# Generated by FakeRAM 2.0
VERSION 5.7 ;
BUSBITCHARS "[]" ;
PROPERTYDEFINITIONS
  MACRO width INTEGER ;
  MACRO depth INTEGER ;
  MACRO banks INTEGER ;
END PROPERTYDEFINITIONS
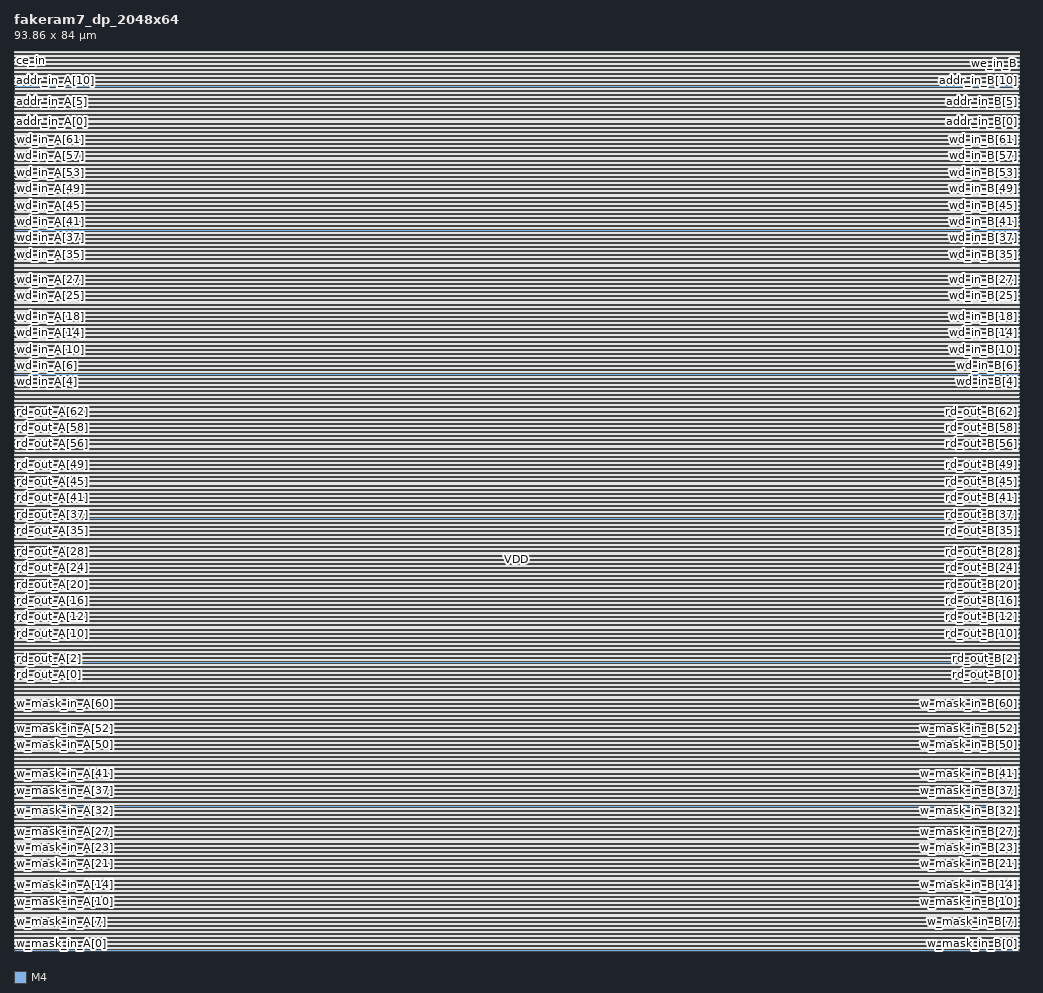
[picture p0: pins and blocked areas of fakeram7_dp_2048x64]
MACRO fakeram7_dp_2048x64
  PROPERTY width 64 ;
  PROPERTY depth 2048 ;
  PROPERTY banks 8 ;
  FOREIGN fakeram7_dp_2048x64 0 0 ;
  SYMMETRY X Y ;
  SIZE 93.860 BY 84.000 ;
  CLASS BLOCK ;
  PIN w_mask_in_A[0]
    DIRECTION INPUT ;
    USE SIGNAL ;
    SHAPE ABUTMENT ;
    PORT
      LAYER M4 ;
      RECT 0.000 0.048 0.024 0.072 ;
    END
  END w_mask_in_A[0]
  PIN w_mask_in_B[0]
    DIRECTION INPUT ;
    USE SIGNAL ;
    SHAPE ABUTMENT ;
    PORT
      LAYER M4 ;
      RECT 93.836 0.048 93.860 0.072 ;
    END
  END w_mask_in_B[0]
  PIN w_mask_in_A[1]
    DIRECTION INPUT ;
    USE SIGNAL ;
    SHAPE ABUTMENT ;
    PORT
      LAYER M4 ;
      RECT 0.000 0.432 0.024 0.456 ;
    END
  END w_mask_in_A[1]
  PIN w_mask_in_B[1]
    DIRECTION INPUT ;
    USE SIGNAL ;
    SHAPE ABUTMENT ;
    PORT
      LAYER M4 ;
      RECT 93.836 0.432 93.860 0.456 ;
    END
  END w_mask_in_B[1]
  PIN w_mask_in_A[2]
    DIRECTION INPUT ;
    USE SIGNAL ;
    SHAPE ABUTMENT ;
    PORT
      LAYER M4 ;
      RECT 0.000 0.816 0.024 0.840 ;
    END
  END w_mask_in_A[2]
  PIN w_mask_in_B[2]
    DIRECTION INPUT ;
    USE SIGNAL ;
    SHAPE ABUTMENT ;
    PORT
      LAYER M4 ;
      RECT 93.836 0.816 93.860 0.840 ;
    END
  END w_mask_in_B[2]
  PIN w_mask_in_A[3]
    DIRECTION INPUT ;
    USE SIGNAL ;
    SHAPE ABUTMENT ;
    PORT
      LAYER M4 ;
      RECT 0.000 1.200 0.024 1.224 ;
    END
  END w_mask_in_A[3]
  PIN w_mask_in_B[3]
    DIRECTION INPUT ;
    USE SIGNAL ;
    SHAPE ABUTMENT ;
    PORT
      LAYER M4 ;
      RECT 93.836 1.200 93.860 1.224 ;
    END
  END w_mask_in_B[3]
  PIN w_mask_in_A[4]
    DIRECTION INPUT ;
    USE SIGNAL ;
    SHAPE ABUTMENT ;
    PORT
      LAYER M4 ;
      RECT 0.000 1.584 0.024 1.608 ;
    END
  END w_mask_in_A[4]
  PIN w_mask_in_B[4]
    DIRECTION INPUT ;
    USE SIGNAL ;
    SHAPE ABUTMENT ;
    PORT
      LAYER M4 ;
      RECT 93.836 1.584 93.860 1.608 ;
    END
  END w_mask_in_B[4]
  PIN w_mask_in_A[5]
    DIRECTION INPUT ;
    USE SIGNAL ;
    SHAPE ABUTMENT ;
    PORT
      LAYER M4 ;
      RECT 0.000 1.968 0.024 1.992 ;
    END
  END w_mask_in_A[5]
  PIN w_mask_in_B[5]
    DIRECTION INPUT ;
    USE SIGNAL ;
    SHAPE ABUTMENT ;
    PORT
      LAYER M4 ;
      RECT 93.836 1.968 93.860 1.992 ;
    END
  END w_mask_in_B[5]
  PIN w_mask_in_A[6]
    DIRECTION INPUT ;
    USE SIGNAL ;
    SHAPE ABUTMENT ;
    PORT
      LAYER M4 ;
      RECT 0.000 2.352 0.024 2.376 ;
    END
  END w_mask_in_A[6]
  PIN w_mask_in_B[6]
    DIRECTION INPUT ;
    USE SIGNAL ;
    SHAPE ABUTMENT ;
    PORT
      LAYER M4 ;
      RECT 93.836 2.352 93.860 2.376 ;
    END
  END w_mask_in_B[6]
  PIN w_mask_in_A[7]
    DIRECTION INPUT ;
    USE SIGNAL ;
    SHAPE ABUTMENT ;
    PORT
      LAYER M4 ;
      RECT 0.000 2.736 0.024 2.760 ;
    END
  END w_mask_in_A[7]
  PIN w_mask_in_B[7]
    DIRECTION INPUT ;
    USE SIGNAL ;
    SHAPE ABUTMENT ;
    PORT
      LAYER M4 ;
      RECT 93.836 2.736 93.860 2.760 ;
    END
  END w_mask_in_B[7]
  PIN w_mask_in_A[8]
    DIRECTION INPUT ;
    USE SIGNAL ;
    SHAPE ABUTMENT ;
    PORT
      LAYER M4 ;
      RECT 0.000 3.120 0.024 3.144 ;
    END
  END w_mask_in_A[8]
  PIN w_mask_in_B[8]
    DIRECTION INPUT ;
    USE SIGNAL ;
    SHAPE ABUTMENT ;
    PORT
      LAYER M4 ;
      RECT 93.836 3.120 93.860 3.144 ;
    END
  END w_mask_in_B[8]
  PIN w_mask_in_A[9]
    DIRECTION INPUT ;
    USE SIGNAL ;
    SHAPE ABUTMENT ;
    PORT
      LAYER M4 ;
      RECT 0.000 3.504 0.024 3.528 ;
    END
  END w_mask_in_A[9]
  PIN w_mask_in_B[9]
    DIRECTION INPUT ;
    USE SIGNAL ;
    SHAPE ABUTMENT ;
    PORT
      LAYER M4 ;
      RECT 93.836 3.504 93.860 3.528 ;
    END
  END w_mask_in_B[9]
  PIN w_mask_in_A[10]
    DIRECTION INPUT ;
    USE SIGNAL ;
    SHAPE ABUTMENT ;
    PORT
      LAYER M4 ;
      RECT 0.000 3.888 0.024 3.912 ;
    END
  END w_mask_in_A[10]
  PIN w_mask_in_B[10]
    DIRECTION INPUT ;
    USE SIGNAL ;
    SHAPE ABUTMENT ;
    PORT
      LAYER M4 ;
      RECT 93.836 3.888 93.860 3.912 ;
    END
  END w_mask_in_B[10]
  PIN w_mask_in_A[11]
    DIRECTION INPUT ;
    USE SIGNAL ;
    SHAPE ABUTMENT ;
    PORT
      LAYER M4 ;
      RECT 0.000 4.272 0.024 4.296 ;
    END
  END w_mask_in_A[11]
  PIN w_mask_in_B[11]
    DIRECTION INPUT ;
    USE SIGNAL ;
    SHAPE ABUTMENT ;
    PORT
      LAYER M4 ;
      RECT 93.836 4.272 93.860 4.296 ;
    END
  END w_mask_in_B[11]
  PIN w_mask_in_A[12]
    DIRECTION INPUT ;
    USE SIGNAL ;
    SHAPE ABUTMENT ;
    PORT
      LAYER M4 ;
      RECT 0.000 4.656 0.024 4.680 ;
    END
  END w_mask_in_A[12]
  PIN w_mask_in_B[12]
    DIRECTION INPUT ;
    USE SIGNAL ;
    SHAPE ABUTMENT ;
    PORT
      LAYER M4 ;
      RECT 93.836 4.656 93.860 4.680 ;
    END
  END w_mask_in_B[12]
  PIN w_mask_in_A[13]
    DIRECTION INPUT ;
    USE SIGNAL ;
    SHAPE ABUTMENT ;
    PORT
      LAYER M4 ;
      RECT 0.000 5.040 0.024 5.064 ;
    END
  END w_mask_in_A[13]
  PIN w_mask_in_B[13]
    DIRECTION INPUT ;
    USE SIGNAL ;
    SHAPE ABUTMENT ;
    PORT
      LAYER M4 ;
      RECT 93.836 5.040 93.860 5.064 ;
    END
  END w_mask_in_B[13]
  PIN w_mask_in_A[14]
    DIRECTION INPUT ;
    USE SIGNAL ;
    SHAPE ABUTMENT ;
    PORT
      LAYER M4 ;
      RECT 0.000 5.424 0.024 5.448 ;
    END
  END w_mask_in_A[14]
  PIN w_mask_in_B[14]
    DIRECTION INPUT ;
    USE SIGNAL ;
    SHAPE ABUTMENT ;
    PORT
      LAYER M4 ;
      RECT 93.836 5.424 93.860 5.448 ;
    END
  END w_mask_in_B[14]
  PIN w_mask_in_A[15]
    DIRECTION INPUT ;
    USE SIGNAL ;
    SHAPE ABUTMENT ;
    PORT
      LAYER M4 ;
      RECT 0.000 5.808 0.024 5.832 ;
    END
  END w_mask_in_A[15]
  PIN w_mask_in_B[15]
    DIRECTION INPUT ;
    USE SIGNAL ;
    SHAPE ABUTMENT ;
    PORT
      LAYER M4 ;
      RECT 93.836 5.808 93.860 5.832 ;
    END
  END w_mask_in_B[15]
  PIN w_mask_in_A[16]
    DIRECTION INPUT ;
    USE SIGNAL ;
    SHAPE ABUTMENT ;
    PORT
      LAYER M4 ;
      RECT 0.000 6.192 0.024 6.216 ;
    END
  END w_mask_in_A[16]
  PIN w_mask_in_B[16]
    DIRECTION INPUT ;
    USE SIGNAL ;
    SHAPE ABUTMENT ;
    PORT
      LAYER M4 ;
      RECT 93.836 6.192 93.860 6.216 ;
    END
  END w_mask_in_B[16]
  PIN w_mask_in_A[17]
    DIRECTION INPUT ;
    USE SIGNAL ;
    SHAPE ABUTMENT ;
    PORT
      LAYER M4 ;
      RECT 0.000 6.576 0.024 6.600 ;
    END
  END w_mask_in_A[17]
  PIN w_mask_in_B[17]
    DIRECTION INPUT ;
    USE SIGNAL ;
    SHAPE ABUTMENT ;
    PORT
      LAYER M4 ;
      RECT 93.836 6.576 93.860 6.600 ;
    END
  END w_mask_in_B[17]
  PIN w_mask_in_A[18]
    DIRECTION INPUT ;
    USE SIGNAL ;
    SHAPE ABUTMENT ;
    PORT
      LAYER M4 ;
      RECT 0.000 6.960 0.024 6.984 ;
    END
  END w_mask_in_A[18]
  PIN w_mask_in_B[18]
    DIRECTION INPUT ;
    USE SIGNAL ;
    SHAPE ABUTMENT ;
    PORT
      LAYER M4 ;
      RECT 93.836 6.960 93.860 6.984 ;
    END
  END w_mask_in_B[18]
  PIN w_mask_in_A[19]
    DIRECTION INPUT ;
    USE SIGNAL ;
    SHAPE ABUTMENT ;
    PORT
      LAYER M4 ;
      RECT 0.000 7.344 0.024 7.368 ;
    END
  END w_mask_in_A[19]
  PIN w_mask_in_B[19]
    DIRECTION INPUT ;
    USE SIGNAL ;
    SHAPE ABUTMENT ;
    PORT
      LAYER M4 ;
      RECT 93.836 7.344 93.860 7.368 ;
    END
  END w_mask_in_B[19]
  PIN w_mask_in_A[20]
    DIRECTION INPUT ;
    USE SIGNAL ;
    SHAPE ABUTMENT ;
    PORT
      LAYER M4 ;
      RECT 0.000 7.728 0.024 7.752 ;
    END
  END w_mask_in_A[20]
  PIN w_mask_in_B[20]
    DIRECTION INPUT ;
    USE SIGNAL ;
    SHAPE ABUTMENT ;
    PORT
      LAYER M4 ;
      RECT 93.836 7.728 93.860 7.752 ;
    END
  END w_mask_in_B[20]
  PIN w_mask_in_A[21]
    DIRECTION INPUT ;
    USE SIGNAL ;
    SHAPE ABUTMENT ;
    PORT
      LAYER M4 ;
      RECT 0.000 8.112 0.024 8.136 ;
    END
  END w_mask_in_A[21]
  PIN w_mask_in_B[21]
    DIRECTION INPUT ;
    USE SIGNAL ;
    SHAPE ABUTMENT ;
    PORT
      LAYER M4 ;
      RECT 93.836 8.112 93.860 8.136 ;
    END
  END w_mask_in_B[21]
  PIN w_mask_in_A[22]
    DIRECTION INPUT ;
    USE SIGNAL ;
    SHAPE ABUTMENT ;
    PORT
      LAYER M4 ;
      RECT 0.000 8.496 0.024 8.520 ;
    END
  END w_mask_in_A[22]
  PIN w_mask_in_B[22]
    DIRECTION INPUT ;
    USE SIGNAL ;
    SHAPE ABUTMENT ;
    PORT
      LAYER M4 ;
      RECT 93.836 8.496 93.860 8.520 ;
    END
  END w_mask_in_B[22]
  PIN w_mask_in_A[23]
    DIRECTION INPUT ;
    USE SIGNAL ;
    SHAPE ABUTMENT ;
    PORT
      LAYER M4 ;
      RECT 0.000 8.880 0.024 8.904 ;
    END
  END w_mask_in_A[23]
  PIN w_mask_in_B[23]
    DIRECTION INPUT ;
    USE SIGNAL ;
    SHAPE ABUTMENT ;
    PORT
      LAYER M4 ;
      RECT 93.836 8.880 93.860 8.904 ;
    END
  END w_mask_in_B[23]
  PIN w_mask_in_A[24]
    DIRECTION INPUT ;
    USE SIGNAL ;
    SHAPE ABUTMENT ;
    PORT
      LAYER M4 ;
      RECT 0.000 9.264 0.024 9.288 ;
    END
  END w_mask_in_A[24]
  PIN w_mask_in_B[24]
    DIRECTION INPUT ;
    USE SIGNAL ;
    SHAPE ABUTMENT ;
    PORT
      LAYER M4 ;
      RECT 93.836 9.264 93.860 9.288 ;
    END
  END w_mask_in_B[24]
  PIN w_mask_in_A[25]
    DIRECTION INPUT ;
    USE SIGNAL ;
    SHAPE ABUTMENT ;
    PORT
      LAYER M4 ;
      RECT 0.000 9.648 0.024 9.672 ;
    END
  END w_mask_in_A[25]
  PIN w_mask_in_B[25]
    DIRECTION INPUT ;
    USE SIGNAL ;
    SHAPE ABUTMENT ;
    PORT
      LAYER M4 ;
      RECT 93.836 9.648 93.860 9.672 ;
    END
  END w_mask_in_B[25]
  PIN w_mask_in_A[26]
    DIRECTION INPUT ;
    USE SIGNAL ;
    SHAPE ABUTMENT ;
    PORT
      LAYER M4 ;
      RECT 0.000 10.032 0.024 10.056 ;
    END
  END w_mask_in_A[26]
  PIN w_mask_in_B[26]
    DIRECTION INPUT ;
    USE SIGNAL ;
    SHAPE ABUTMENT ;
    PORT
      LAYER M4 ;
      RECT 93.836 10.032 93.860 10.056 ;
    END
  END w_mask_in_B[26]
  PIN w_mask_in_A[27]
    DIRECTION INPUT ;
    USE SIGNAL ;
    SHAPE ABUTMENT ;
    PORT
      LAYER M4 ;
      RECT 0.000 10.416 0.024 10.440 ;
    END
  END w_mask_in_A[27]
  PIN w_mask_in_B[27]
    DIRECTION INPUT ;
    USE SIGNAL ;
    SHAPE ABUTMENT ;
    PORT
      LAYER M4 ;
      RECT 93.836 10.416 93.860 10.440 ;
    END
  END w_mask_in_B[27]
  PIN w_mask_in_A[28]
    DIRECTION INPUT ;
    USE SIGNAL ;
    SHAPE ABUTMENT ;
    PORT
      LAYER M4 ;
      RECT 0.000 10.800 0.024 10.824 ;
    END
  END w_mask_in_A[28]
  PIN w_mask_in_B[28]
    DIRECTION INPUT ;
    USE SIGNAL ;
    SHAPE ABUTMENT ;
    PORT
      LAYER M4 ;
      RECT 93.836 10.800 93.860 10.824 ;
    END
  END w_mask_in_B[28]
  PIN w_mask_in_A[29]
    DIRECTION INPUT ;
    USE SIGNAL ;
    SHAPE ABUTMENT ;
    PORT
      LAYER M4 ;
      RECT 0.000 11.184 0.024 11.208 ;
    END
  END w_mask_in_A[29]
  PIN w_mask_in_B[29]
    DIRECTION INPUT ;
    USE SIGNAL ;
    SHAPE ABUTMENT ;
    PORT
      LAYER M4 ;
      RECT 93.836 11.184 93.860 11.208 ;
    END
  END w_mask_in_B[29]
  PIN w_mask_in_A[30]
    DIRECTION INPUT ;
    USE SIGNAL ;
    SHAPE ABUTMENT ;
    PORT
      LAYER M4 ;
      RECT 0.000 11.568 0.024 11.592 ;
    END
  END w_mask_in_A[30]
  PIN w_mask_in_B[30]
    DIRECTION INPUT ;
    USE SIGNAL ;
    SHAPE ABUTMENT ;
    PORT
      LAYER M4 ;
      RECT 93.836 11.568 93.860 11.592 ;
    END
  END w_mask_in_B[30]
  PIN w_mask_in_A[31]
    DIRECTION INPUT ;
    USE SIGNAL ;
    SHAPE ABUTMENT ;
    PORT
      LAYER M4 ;
      RECT 0.000 11.952 0.024 11.976 ;
    END
  END w_mask_in_A[31]
  PIN w_mask_in_B[31]
    DIRECTION INPUT ;
    USE SIGNAL ;
    SHAPE ABUTMENT ;
    PORT
      LAYER M4 ;
      RECT 93.836 11.952 93.860 11.976 ;
    END
  END w_mask_in_B[31]
  PIN w_mask_in_A[32]
    DIRECTION INPUT ;
    USE SIGNAL ;
    SHAPE ABUTMENT ;
    PORT
      LAYER M4 ;
      RECT 0.000 12.336 0.024 12.360 ;
    END
  END w_mask_in_A[32]
  PIN w_mask_in_B[32]
    DIRECTION INPUT ;
    USE SIGNAL ;
    SHAPE ABUTMENT ;
    PORT
      LAYER M4 ;
      RECT 93.836 12.336 93.860 12.360 ;
    END
  END w_mask_in_B[32]
  PIN w_mask_in_A[33]
    DIRECTION INPUT ;
    USE SIGNAL ;
    SHAPE ABUTMENT ;
    PORT
      LAYER M4 ;
      RECT 0.000 12.720 0.024 12.744 ;
    END
  END w_mask_in_A[33]
  PIN w_mask_in_B[33]
    DIRECTION INPUT ;
    USE SIGNAL ;
    SHAPE ABUTMENT ;
    PORT
      LAYER M4 ;
      RECT 93.836 12.720 93.860 12.744 ;
    END
  END w_mask_in_B[33]
  PIN w_mask_in_A[34]
    DIRECTION INPUT ;
    USE SIGNAL ;
    SHAPE ABUTMENT ;
    PORT
      LAYER M4 ;
      RECT 0.000 13.104 0.024 13.128 ;
    END
  END w_mask_in_A[34]
  PIN w_mask_in_B[34]
    DIRECTION INPUT ;
    USE SIGNAL ;
    SHAPE ABUTMENT ;
    PORT
      LAYER M4 ;
      RECT 93.836 13.104 93.860 13.128 ;
    END
  END w_mask_in_B[34]
  PIN w_mask_in_A[35]
    DIRECTION INPUT ;
    USE SIGNAL ;
    SHAPE ABUTMENT ;
    PORT
      LAYER M4 ;
      RECT 0.000 13.488 0.024 13.512 ;
    END
  END w_mask_in_A[35]
  PIN w_mask_in_B[35]
    DIRECTION INPUT ;
    USE SIGNAL ;
    SHAPE ABUTMENT ;
    PORT
      LAYER M4 ;
      RECT 93.836 13.488 93.860 13.512 ;
    END
  END w_mask_in_B[35]
  PIN w_mask_in_A[36]
    DIRECTION INPUT ;
    USE SIGNAL ;
    SHAPE ABUTMENT ;
    PORT
      LAYER M4 ;
      RECT 0.000 13.872 0.024 13.896 ;
    END
  END w_mask_in_A[36]
  PIN w_mask_in_B[36]
    DIRECTION INPUT ;
    USE SIGNAL ;
    SHAPE ABUTMENT ;
    PORT
      LAYER M4 ;
      RECT 93.836 13.872 93.860 13.896 ;
    END
  END w_mask_in_B[36]
  PIN w_mask_in_A[37]
    DIRECTION INPUT ;
    USE SIGNAL ;
    SHAPE ABUTMENT ;
    PORT
      LAYER M4 ;
      RECT 0.000 14.256 0.024 14.280 ;
    END
  END w_mask_in_A[37]
  PIN w_mask_in_B[37]
    DIRECTION INPUT ;
    USE SIGNAL ;
    SHAPE ABUTMENT ;
    PORT
      LAYER M4 ;
      RECT 93.836 14.256 93.860 14.280 ;
    END
  END w_mask_in_B[37]
  PIN w_mask_in_A[38]
    DIRECTION INPUT ;
    USE SIGNAL ;
    SHAPE ABUTMENT ;
    PORT
      LAYER M4 ;
      RECT 0.000 14.640 0.024 14.664 ;
    END
  END w_mask_in_A[38]
  PIN w_mask_in_B[38]
    DIRECTION INPUT ;
    USE SIGNAL ;
    SHAPE ABUTMENT ;
    PORT
      LAYER M4 ;
      RECT 93.836 14.640 93.860 14.664 ;
    END
  END w_mask_in_B[38]
  PIN w_mask_in_A[39]
    DIRECTION INPUT ;
    USE SIGNAL ;
    SHAPE ABUTMENT ;
    PORT
      LAYER M4 ;
      RECT 0.000 15.024 0.024 15.048 ;
    END
  END w_mask_in_A[39]
  PIN w_mask_in_B[39]
    DIRECTION INPUT ;
    USE SIGNAL ;
    SHAPE ABUTMENT ;
    PORT
      LAYER M4 ;
      RECT 93.836 15.024 93.860 15.048 ;
    END
  END w_mask_in_B[39]
  PIN w_mask_in_A[40]
    DIRECTION INPUT ;
    USE SIGNAL ;
    SHAPE ABUTMENT ;
    PORT
      LAYER M4 ;
      RECT 0.000 15.408 0.024 15.432 ;
    END
  END w_mask_in_A[40]
  PIN w_mask_in_B[40]
    DIRECTION INPUT ;
    USE SIGNAL ;
    SHAPE ABUTMENT ;
    PORT
      LAYER M4 ;
      RECT 93.836 15.408 93.860 15.432 ;
    END
  END w_mask_in_B[40]
  PIN w_mask_in_A[41]
    DIRECTION INPUT ;
    USE SIGNAL ;
    SHAPE ABUTMENT ;
    PORT
      LAYER M4 ;
      RECT 0.000 15.792 0.024 15.816 ;
    END
  END w_mask_in_A[41]
  PIN w_mask_in_B[41]
    DIRECTION INPUT ;
    USE SIGNAL ;
    SHAPE ABUTMENT ;
    PORT
      LAYER M4 ;
      RECT 93.836 15.792 93.860 15.816 ;
    END
  END w_mask_in_B[41]
  PIN w_mask_in_A[42]
    DIRECTION INPUT ;
    USE SIGNAL ;
    SHAPE ABUTMENT ;
    PORT
      LAYER M4 ;
      RECT 0.000 16.176 0.024 16.200 ;
    END
  END w_mask_in_A[42]
  PIN w_mask_in_B[42]
    DIRECTION INPUT ;
    USE SIGNAL ;
    SHAPE ABUTMENT ;
    PORT
      LAYER M4 ;
      RECT 93.836 16.176 93.860 16.200 ;
    END
  END w_mask_in_B[42]
  PIN w_mask_in_A[43]
    DIRECTION INPUT ;
    USE SIGNAL ;
    SHAPE ABUTMENT ;
    PORT
      LAYER M4 ;
      RECT 0.000 16.560 0.024 16.584 ;
    END
  END w_mask_in_A[43]
  PIN w_mask_in_B[43]
    DIRECTION INPUT ;
    USE SIGNAL ;
    SHAPE ABUTMENT ;
    PORT
      LAYER M4 ;
      RECT 93.836 16.560 93.860 16.584 ;
    END
  END w_mask_in_B[43]
  PIN w_mask_in_A[44]
    DIRECTION INPUT ;
    USE SIGNAL ;
    SHAPE ABUTMENT ;
    PORT
      LAYER M4 ;
      RECT 0.000 16.944 0.024 16.968 ;
    END
  END w_mask_in_A[44]
  PIN w_mask_in_B[44]
    DIRECTION INPUT ;
    USE SIGNAL ;
    SHAPE ABUTMENT ;
    PORT
      LAYER M4 ;
      RECT 93.836 16.944 93.860 16.968 ;
    END
  END w_mask_in_B[44]
  PIN w_mask_in_A[45]
    DIRECTION INPUT ;
    USE SIGNAL ;
    SHAPE ABUTMENT ;
    PORT
      LAYER M4 ;
      RECT 0.000 17.328 0.024 17.352 ;
    END
  END w_mask_in_A[45]
  PIN w_mask_in_B[45]
    DIRECTION INPUT ;
    USE SIGNAL ;
    SHAPE ABUTMENT ;
    PORT
      LAYER M4 ;
      RECT 93.836 17.328 93.860 17.352 ;
    END
  END w_mask_in_B[45]
  PIN w_mask_in_A[46]
    DIRECTION INPUT ;
    USE SIGNAL ;
    SHAPE ABUTMENT ;
    PORT
      LAYER M4 ;
      RECT 0.000 17.712 0.024 17.736 ;
    END
  END w_mask_in_A[46]
  PIN w_mask_in_B[46]
    DIRECTION INPUT ;
    USE SIGNAL ;
    SHAPE ABUTMENT ;
    PORT
      LAYER M4 ;
      RECT 93.836 17.712 93.860 17.736 ;
    END
  END w_mask_in_B[46]
  PIN w_mask_in_A[47]
    DIRECTION INPUT ;
    USE SIGNAL ;
    SHAPE ABUTMENT ;
    PORT
      LAYER M4 ;
      RECT 0.000 18.096 0.024 18.120 ;
    END
  END w_mask_in_A[47]
  PIN w_mask_in_B[47]
    DIRECTION INPUT ;
    USE SIGNAL ;
    SHAPE ABUTMENT ;
    PORT
      LAYER M4 ;
      RECT 93.836 18.096 93.860 18.120 ;
    END
  END w_mask_in_B[47]
  PIN w_mask_in_A[48]
    DIRECTION INPUT ;
    USE SIGNAL ;
    SHAPE ABUTMENT ;
    PORT
      LAYER M4 ;
      RECT 0.000 18.480 0.024 18.504 ;
    END
  END w_mask_in_A[48]
  PIN w_mask_in_B[48]
    DIRECTION INPUT ;
    USE SIGNAL ;
    SHAPE ABUTMENT ;
    PORT
      LAYER M4 ;
      RECT 93.836 18.480 93.860 18.504 ;
    END
  END w_mask_in_B[48]
  PIN w_mask_in_A[49]
    DIRECTION INPUT ;
    USE SIGNAL ;
    SHAPE ABUTMENT ;
    PORT
      LAYER M4 ;
      RECT 0.000 18.864 0.024 18.888 ;
    END
  END w_mask_in_A[49]
  PIN w_mask_in_B[49]
    DIRECTION INPUT ;
    USE SIGNAL ;
    SHAPE ABUTMENT ;
    PORT
      LAYER M4 ;
      RECT 93.836 18.864 93.860 18.888 ;
    END
  END w_mask_in_B[49]
  PIN w_mask_in_A[50]
    DIRECTION INPUT ;
    USE SIGNAL ;
    SHAPE ABUTMENT ;
    PORT
      LAYER M4 ;
      RECT 0.000 19.248 0.024 19.272 ;
    END
  END w_mask_in_A[50]
  PIN w_mask_in_B[50]
    DIRECTION INPUT ;
    USE SIGNAL ;
    SHAPE ABUTMENT ;
    PORT
      LAYER M4 ;
      RECT 93.836 19.248 93.860 19.272 ;
    END
  END w_mask_in_B[50]
  PIN w_mask_in_A[51]
    DIRECTION INPUT ;
    USE SIGNAL ;
    SHAPE ABUTMENT ;
    PORT
      LAYER M4 ;
      RECT 0.000 19.632 0.024 19.656 ;
    END
  END w_mask_in_A[51]
  PIN w_mask_in_B[51]
    DIRECTION INPUT ;
    USE SIGNAL ;
    SHAPE ABUTMENT ;
    PORT
      LAYER M4 ;
      RECT 93.836 19.632 93.860 19.656 ;
    END
  END w_mask_in_B[51]
  PIN w_mask_in_A[52]
    DIRECTION INPUT ;
    USE SIGNAL ;
    SHAPE ABUTMENT ;
    PORT
      LAYER M4 ;
      RECT 0.000 20.016 0.024 20.040 ;
    END
  END w_mask_in_A[52]
  PIN w_mask_in_B[52]
    DIRECTION INPUT ;
    USE SIGNAL ;
    SHAPE ABUTMENT ;
    PORT
      LAYER M4 ;
      RECT 93.836 20.016 93.860 20.040 ;
    END
  END w_mask_in_B[52]
  PIN w_mask_in_A[53]
    DIRECTION INPUT ;
    USE SIGNAL ;
    SHAPE ABUTMENT ;
    PORT
      LAYER M4 ;
      RECT 0.000 20.400 0.024 20.424 ;
    END
  END w_mask_in_A[53]
  PIN w_mask_in_B[53]
    DIRECTION INPUT ;
    USE SIGNAL ;
    SHAPE ABUTMENT ;
    PORT
      LAYER M4 ;
      RECT 93.836 20.400 93.860 20.424 ;
    END
  END w_mask_in_B[53]
  PIN w_mask_in_A[54]
    DIRECTION INPUT ;
    USE SIGNAL ;
    SHAPE ABUTMENT ;
    PORT
      LAYER M4 ;
      RECT 0.000 20.784 0.024 20.808 ;
    END
  END w_mask_in_A[54]
  PIN w_mask_in_B[54]
    DIRECTION INPUT ;
    USE SIGNAL ;
    SHAPE ABUTMENT ;
    PORT
      LAYER M4 ;
      RECT 93.836 20.784 93.860 20.808 ;
    END
  END w_mask_in_B[54]
  PIN w_mask_in_A[55]
    DIRECTION INPUT ;
    USE SIGNAL ;
    SHAPE ABUTMENT ;
    PORT
      LAYER M4 ;
      RECT 0.000 21.168 0.024 21.192 ;
    END
  END w_mask_in_A[55]
  PIN w_mask_in_B[55]
    DIRECTION INPUT ;
    USE SIGNAL ;
    SHAPE ABUTMENT ;
    PORT
      LAYER M4 ;
      RECT 93.836 21.168 93.860 21.192 ;
    END
  END w_mask_in_B[55]
  PIN w_mask_in_A[56]
    DIRECTION INPUT ;
    USE SIGNAL ;
    SHAPE ABUTMENT ;
    PORT
      LAYER M4 ;
      RECT 0.000 21.552 0.024 21.576 ;
    END
  END w_mask_in_A[56]
  PIN w_mask_in_B[56]
    DIRECTION INPUT ;
    USE SIGNAL ;
    SHAPE ABUTMENT ;
    PORT
      LAYER M4 ;
      RECT 93.836 21.552 93.860 21.576 ;
    END
  END w_mask_in_B[56]
  PIN w_mask_in_A[57]
    DIRECTION INPUT ;
    USE SIGNAL ;
    SHAPE ABUTMENT ;
    PORT
      LAYER M4 ;
      RECT 0.000 21.936 0.024 21.960 ;
    END
  END w_mask_in_A[57]
  PIN w_mask_in_B[57]
    DIRECTION INPUT ;
    USE SIGNAL ;
    SHAPE ABUTMENT ;
    PORT
      LAYER M4 ;
      RECT 93.836 21.936 93.860 21.960 ;
    END
  END w_mask_in_B[57]
  PIN w_mask_in_A[58]
    DIRECTION INPUT ;
    USE SIGNAL ;
    SHAPE ABUTMENT ;
    PORT
      LAYER M4 ;
      RECT 0.000 22.320 0.024 22.344 ;
    END
  END w_mask_in_A[58]
  PIN w_mask_in_B[58]
    DIRECTION INPUT ;
    USE SIGNAL ;
    SHAPE ABUTMENT ;
    PORT
      LAYER M4 ;
      RECT 93.836 22.320 93.860 22.344 ;
    END
  END w_mask_in_B[58]
  PIN w_mask_in_A[59]
    DIRECTION INPUT ;
    USE SIGNAL ;
    SHAPE ABUTMENT ;
    PORT
      LAYER M4 ;
      RECT 0.000 22.704 0.024 22.728 ;
    END
  END w_mask_in_A[59]
  PIN w_mask_in_B[59]
    DIRECTION INPUT ;
    USE SIGNAL ;
    SHAPE ABUTMENT ;
    PORT
      LAYER M4 ;
      RECT 93.836 22.704 93.860 22.728 ;
    END
  END w_mask_in_B[59]
  PIN w_mask_in_A[60]
    DIRECTION INPUT ;
    USE SIGNAL ;
    SHAPE ABUTMENT ;
    PORT
      LAYER M4 ;
      RECT 0.000 23.088 0.024 23.112 ;
    END
  END w_mask_in_A[60]
  PIN w_mask_in_B[60]
    DIRECTION INPUT ;
    USE SIGNAL ;
    SHAPE ABUTMENT ;
    PORT
      LAYER M4 ;
      RECT 93.836 23.088 93.860 23.112 ;
    END
  END w_mask_in_B[60]
  PIN w_mask_in_A[61]
    DIRECTION INPUT ;
    USE SIGNAL ;
    SHAPE ABUTMENT ;
    PORT
      LAYER M4 ;
      RECT 0.000 23.472 0.024 23.496 ;
    END
  END w_mask_in_A[61]
  PIN w_mask_in_B[61]
    DIRECTION INPUT ;
    USE SIGNAL ;
    SHAPE ABUTMENT ;
    PORT
      LAYER M4 ;
      RECT 93.836 23.472 93.860 23.496 ;
    END
  END w_mask_in_B[61]
  PIN w_mask_in_A[62]
    DIRECTION INPUT ;
    USE SIGNAL ;
    SHAPE ABUTMENT ;
    PORT
      LAYER M4 ;
      RECT 0.000 23.856 0.024 23.880 ;
    END
  END w_mask_in_A[62]
  PIN w_mask_in_B[62]
    DIRECTION INPUT ;
    USE SIGNAL ;
    SHAPE ABUTMENT ;
    PORT
      LAYER M4 ;
      RECT 93.836 23.856 93.860 23.880 ;
    END
  END w_mask_in_B[62]
  PIN w_mask_in_A[63]
    DIRECTION INPUT ;
    USE SIGNAL ;
    SHAPE ABUTMENT ;
    PORT
      LAYER M4 ;
      RECT 0.000 24.240 0.024 24.264 ;
    END
  END w_mask_in_A[63]
  PIN w_mask_in_B[63]
    DIRECTION INPUT ;
    USE SIGNAL ;
    SHAPE ABUTMENT ;
    PORT
      LAYER M4 ;
      RECT 93.836 24.240 93.860 24.264 ;
    END
  END w_mask_in_B[63]
  PIN rd_out_A[0]
    DIRECTION OUTPUT ;
    USE SIGNAL ;
    SHAPE ABUTMENT ;
    PORT
      LAYER M4 ;
      RECT 0.000 25.824 0.024 25.848 ;
    END
  END rd_out_A[0]
  PIN rd_out_B[0]
    DIRECTION OUTPUT ;
    USE SIGNAL ;
    SHAPE ABUTMENT ;
    PORT
      LAYER M4 ;
      RECT 93.836 25.824 93.860 25.848 ;
    END
  END rd_out_B[0]
  PIN rd_out_A[1]
    DIRECTION OUTPUT ;
    USE SIGNAL ;
    SHAPE ABUTMENT ;
    PORT
      LAYER M4 ;
      RECT 0.000 26.208 0.024 26.232 ;
    END
  END rd_out_A[1]
  PIN rd_out_B[1]
    DIRECTION OUTPUT ;
    USE SIGNAL ;
    SHAPE ABUTMENT ;
    PORT
      LAYER M4 ;
      RECT 93.836 26.208 93.860 26.232 ;
    END
  END rd_out_B[1]
  PIN rd_out_A[2]
    DIRECTION OUTPUT ;
    USE SIGNAL ;
    SHAPE ABUTMENT ;
    PORT
      LAYER M4 ;
      RECT 0.000 26.592 0.024 26.616 ;
    END
  END rd_out_A[2]
  PIN rd_out_B[2]
    DIRECTION OUTPUT ;
    USE SIGNAL ;
    SHAPE ABUTMENT ;
    PORT
      LAYER M4 ;
      RECT 93.836 26.592 93.860 26.616 ;
    END
  END rd_out_B[2]
  PIN rd_out_A[3]
    DIRECTION OUTPUT ;
    USE SIGNAL ;
    SHAPE ABUTMENT ;
    PORT
      LAYER M4 ;
      RECT 0.000 26.976 0.024 27.000 ;
    END
  END rd_out_A[3]
  PIN rd_out_B[3]
    DIRECTION OUTPUT ;
    USE SIGNAL ;
    SHAPE ABUTMENT ;
    PORT
      LAYER M4 ;
      RECT 93.836 26.976 93.860 27.000 ;
    END
  END rd_out_B[3]
  PIN rd_out_A[4]
    DIRECTION OUTPUT ;
    USE SIGNAL ;
    SHAPE ABUTMENT ;
    PORT
      LAYER M4 ;
      RECT 0.000 27.360 0.024 27.384 ;
    END
  END rd_out_A[4]
  PIN rd_out_B[4]
    DIRECTION OUTPUT ;
    USE SIGNAL ;
    SHAPE ABUTMENT ;
    PORT
      LAYER M4 ;
      RECT 93.836 27.360 93.860 27.384 ;
    END
  END rd_out_B[4]
  PIN rd_out_A[5]
    DIRECTION OUTPUT ;
    USE SIGNAL ;
    SHAPE ABUTMENT ;
    PORT
      LAYER M4 ;
      RECT 0.000 27.744 0.024 27.768 ;
    END
  END rd_out_A[5]
  PIN rd_out_B[5]
    DIRECTION OUTPUT ;
    USE SIGNAL ;
    SHAPE ABUTMENT ;
    PORT
      LAYER M4 ;
      RECT 93.836 27.744 93.860 27.768 ;
    END
  END rd_out_B[5]
  PIN rd_out_A[6]
    DIRECTION OUTPUT ;
    USE SIGNAL ;
    SHAPE ABUTMENT ;
    PORT
      LAYER M4 ;
      RECT 0.000 28.128 0.024 28.152 ;
    END
  END rd_out_A[6]
  PIN rd_out_B[6]
    DIRECTION OUTPUT ;
    USE SIGNAL ;
    SHAPE ABUTMENT ;
    PORT
      LAYER M4 ;
      RECT 93.836 28.128 93.860 28.152 ;
    END
  END rd_out_B[6]
  PIN rd_out_A[7]
    DIRECTION OUTPUT ;
    USE SIGNAL ;
    SHAPE ABUTMENT ;
    PORT
      LAYER M4 ;
      RECT 0.000 28.512 0.024 28.536 ;
    END
  END rd_out_A[7]
  PIN rd_out_B[7]
    DIRECTION OUTPUT ;
    USE SIGNAL ;
    SHAPE ABUTMENT ;
    PORT
      LAYER M4 ;
      RECT 93.836 28.512 93.860 28.536 ;
    END
  END rd_out_B[7]
  PIN rd_out_A[8]
    DIRECTION OUTPUT ;
    USE SIGNAL ;
    SHAPE ABUTMENT ;
    PORT
      LAYER M4 ;
      RECT 0.000 28.896 0.024 28.920 ;
    END
  END rd_out_A[8]
  PIN rd_out_B[8]
    DIRECTION OUTPUT ;
    USE SIGNAL ;
    SHAPE ABUTMENT ;
    PORT
      LAYER M4 ;
      RECT 93.836 28.896 93.860 28.920 ;
    END
  END rd_out_B[8]
  PIN rd_out_A[9]
    DIRECTION OUTPUT ;
    USE SIGNAL ;
    SHAPE ABUTMENT ;
    PORT
      LAYER M4 ;
      RECT 0.000 29.280 0.024 29.304 ;
    END
  END rd_out_A[9]
  PIN rd_out_B[9]
    DIRECTION OUTPUT ;
    USE SIGNAL ;
    SHAPE ABUTMENT ;
    PORT
      LAYER M4 ;
      RECT 93.836 29.280 93.860 29.304 ;
    END
  END rd_out_B[9]
  PIN rd_out_A[10]
    DIRECTION OUTPUT ;
    USE SIGNAL ;
    SHAPE ABUTMENT ;
    PORT
      LAYER M4 ;
      RECT 0.000 29.664 0.024 29.688 ;
    END
  END rd_out_A[10]
  PIN rd_out_B[10]
    DIRECTION OUTPUT ;
    USE SIGNAL ;
    SHAPE ABUTMENT ;
    PORT
      LAYER M4 ;
      RECT 93.836 29.664 93.860 29.688 ;
    END
  END rd_out_B[10]
  PIN rd_out_A[11]
    DIRECTION OUTPUT ;
    USE SIGNAL ;
    SHAPE ABUTMENT ;
    PORT
      LAYER M4 ;
      RECT 0.000 30.048 0.024 30.072 ;
    END
  END rd_out_A[11]
  PIN rd_out_B[11]
    DIRECTION OUTPUT ;
    USE SIGNAL ;
    SHAPE ABUTMENT ;
    PORT
      LAYER M4 ;
      RECT 93.836 30.048 93.860 30.072 ;
    END
  END rd_out_B[11]
  PIN rd_out_A[12]
    DIRECTION OUTPUT ;
    USE SIGNAL ;
    SHAPE ABUTMENT ;
    PORT
      LAYER M4 ;
      RECT 0.000 30.432 0.024 30.456 ;
    END
  END rd_out_A[12]
  PIN rd_out_B[12]
    DIRECTION OUTPUT ;
    USE SIGNAL ;
    SHAPE ABUTMENT ;
    PORT
      LAYER M4 ;
      RECT 93.836 30.432 93.860 30.456 ;
    END
  END rd_out_B[12]
  PIN rd_out_A[13]
    DIRECTION OUTPUT ;
    USE SIGNAL ;
    SHAPE ABUTMENT ;
    PORT
      LAYER M4 ;
      RECT 0.000 30.816 0.024 30.840 ;
    END
  END rd_out_A[13]
  PIN rd_out_B[13]
    DIRECTION OUTPUT ;
    USE SIGNAL ;
    SHAPE ABUTMENT ;
    PORT
      LAYER M4 ;
      RECT 93.836 30.816 93.860 30.840 ;
    END
  END rd_out_B[13]
  PIN rd_out_A[14]
    DIRECTION OUTPUT ;
    USE SIGNAL ;
    SHAPE ABUTMENT ;
    PORT
      LAYER M4 ;
      RECT 0.000 31.200 0.024 31.224 ;
    END
  END rd_out_A[14]
  PIN rd_out_B[14]
    DIRECTION OUTPUT ;
    USE SIGNAL ;
    SHAPE ABUTMENT ;
    PORT
      LAYER M4 ;
      RECT 93.836 31.200 93.860 31.224 ;
    END
  END rd_out_B[14]
  PIN rd_out_A[15]
    DIRECTION OUTPUT ;
    USE SIGNAL ;
    SHAPE ABUTMENT ;
    PORT
      LAYER M4 ;
      RECT 0.000 31.584 0.024 31.608 ;
    END
  END rd_out_A[15]
  PIN rd_out_B[15]
    DIRECTION OUTPUT ;
    USE SIGNAL ;
    SHAPE ABUTMENT ;
    PORT
      LAYER M4 ;
      RECT 93.836 31.584 93.860 31.608 ;
    END
  END rd_out_B[15]
  PIN rd_out_A[16]
    DIRECTION OUTPUT ;
    USE SIGNAL ;
    SHAPE ABUTMENT ;
    PORT
      LAYER M4 ;
      RECT 0.000 31.968 0.024 31.992 ;
    END
  END rd_out_A[16]
  PIN rd_out_B[16]
    DIRECTION OUTPUT ;
    USE SIGNAL ;
    SHAPE ABUTMENT ;
    PORT
      LAYER M4 ;
      RECT 93.836 31.968 93.860 31.992 ;
    END
  END rd_out_B[16]
  PIN rd_out_A[17]
    DIRECTION OUTPUT ;
    USE SIGNAL ;
    SHAPE ABUTMENT ;
    PORT
      LAYER M4 ;
      RECT 0.000 32.352 0.024 32.376 ;
    END
  END rd_out_A[17]
  PIN rd_out_B[17]
    DIRECTION OUTPUT ;
    USE SIGNAL ;
    SHAPE ABUTMENT ;
    PORT
      LAYER M4 ;
      RECT 93.836 32.352 93.860 32.376 ;
    END
  END rd_out_B[17]
  PIN rd_out_A[18]
    DIRECTION OUTPUT ;
    USE SIGNAL ;
    SHAPE ABUTMENT ;
    PORT
      LAYER M4 ;
      RECT 0.000 32.736 0.024 32.760 ;
    END
  END rd_out_A[18]
  PIN rd_out_B[18]
    DIRECTION OUTPUT ;
    USE SIGNAL ;
    SHAPE ABUTMENT ;
    PORT
      LAYER M4 ;
      RECT 93.836 32.736 93.860 32.760 ;
    END
  END rd_out_B[18]
  PIN rd_out_A[19]
    DIRECTION OUTPUT ;
    USE SIGNAL ;
    SHAPE ABUTMENT ;
    PORT
      LAYER M4 ;
      RECT 0.000 33.120 0.024 33.144 ;
    END
  END rd_out_A[19]
  PIN rd_out_B[19]
    DIRECTION OUTPUT ;
    USE SIGNAL ;
    SHAPE ABUTMENT ;
    PORT
      LAYER M4 ;
      RECT 93.836 33.120 93.860 33.144 ;
    END
  END rd_out_B[19]
  PIN rd_out_A[20]
    DIRECTION OUTPUT ;
    USE SIGNAL ;
    SHAPE ABUTMENT ;
    PORT
      LAYER M4 ;
      RECT 0.000 33.504 0.024 33.528 ;
    END
  END rd_out_A[20]
  PIN rd_out_B[20]
    DIRECTION OUTPUT ;
    USE SIGNAL ;
    SHAPE ABUTMENT ;
    PORT
      LAYER M4 ;
      RECT 93.836 33.504 93.860 33.528 ;
    END
  END rd_out_B[20]
  PIN rd_out_A[21]
    DIRECTION OUTPUT ;
    USE SIGNAL ;
    SHAPE ABUTMENT ;
    PORT
      LAYER M4 ;
      RECT 0.000 33.888 0.024 33.912 ;
    END
  END rd_out_A[21]
  PIN rd_out_B[21]
    DIRECTION OUTPUT ;
    USE SIGNAL ;
    SHAPE ABUTMENT ;
    PORT
      LAYER M4 ;
      RECT 93.836 33.888 93.860 33.912 ;
    END
  END rd_out_B[21]
  PIN rd_out_A[22]
    DIRECTION OUTPUT ;
    USE SIGNAL ;
    SHAPE ABUTMENT ;
    PORT
      LAYER M4 ;
      RECT 0.000 34.272 0.024 34.296 ;
    END
  END rd_out_A[22]
  PIN rd_out_B[22]
    DIRECTION OUTPUT ;
    USE SIGNAL ;
    SHAPE ABUTMENT ;
    PORT
      LAYER M4 ;
      RECT 93.836 34.272 93.860 34.296 ;
    END
  END rd_out_B[22]
  PIN rd_out_A[23]
    DIRECTION OUTPUT ;
    USE SIGNAL ;
    SHAPE ABUTMENT ;
    PORT
      LAYER M4 ;
      RECT 0.000 34.656 0.024 34.680 ;
    END
  END rd_out_A[23]
  PIN rd_out_B[23]
    DIRECTION OUTPUT ;
    USE SIGNAL ;
    SHAPE ABUTMENT ;
    PORT
      LAYER M4 ;
      RECT 93.836 34.656 93.860 34.680 ;
    END
  END rd_out_B[23]
  PIN rd_out_A[24]
    DIRECTION OUTPUT ;
    USE SIGNAL ;
    SHAPE ABUTMENT ;
    PORT
      LAYER M4 ;
      RECT 0.000 35.040 0.024 35.064 ;
    END
  END rd_out_A[24]
  PIN rd_out_B[24]
    DIRECTION OUTPUT ;
    USE SIGNAL ;
    SHAPE ABUTMENT ;
    PORT
      LAYER M4 ;
      RECT 93.836 35.040 93.860 35.064 ;
    END
  END rd_out_B[24]
  PIN rd_out_A[25]
    DIRECTION OUTPUT ;
    USE SIGNAL ;
    SHAPE ABUTMENT ;
    PORT
      LAYER M4 ;
      RECT 0.000 35.424 0.024 35.448 ;
    END
  END rd_out_A[25]
  PIN rd_out_B[25]
    DIRECTION OUTPUT ;
    USE SIGNAL ;
    SHAPE ABUTMENT ;
    PORT
      LAYER M4 ;
      RECT 93.836 35.424 93.860 35.448 ;
    END
  END rd_out_B[25]
  PIN rd_out_A[26]
    DIRECTION OUTPUT ;
    USE SIGNAL ;
    SHAPE ABUTMENT ;
    PORT
      LAYER M4 ;
      RECT 0.000 35.808 0.024 35.832 ;
    END
  END rd_out_A[26]
  PIN rd_out_B[26]
    DIRECTION OUTPUT ;
    USE SIGNAL ;
    SHAPE ABUTMENT ;
    PORT
      LAYER M4 ;
      RECT 93.836 35.808 93.860 35.832 ;
    END
  END rd_out_B[26]
  PIN rd_out_A[27]
    DIRECTION OUTPUT ;
    USE SIGNAL ;
    SHAPE ABUTMENT ;
    PORT
      LAYER M4 ;
      RECT 0.000 36.192 0.024 36.216 ;
    END
  END rd_out_A[27]
  PIN rd_out_B[27]
    DIRECTION OUTPUT ;
    USE SIGNAL ;
    SHAPE ABUTMENT ;
    PORT
      LAYER M4 ;
      RECT 93.836 36.192 93.860 36.216 ;
    END
  END rd_out_B[27]
  PIN rd_out_A[28]
    DIRECTION OUTPUT ;
    USE SIGNAL ;
    SHAPE ABUTMENT ;
    PORT
      LAYER M4 ;
      RECT 0.000 36.576 0.024 36.600 ;
    END
  END rd_out_A[28]
  PIN rd_out_B[28]
    DIRECTION OUTPUT ;
    USE SIGNAL ;
    SHAPE ABUTMENT ;
    PORT
      LAYER M4 ;
      RECT 93.836 36.576 93.860 36.600 ;
    END
  END rd_out_B[28]
  PIN rd_out_A[29]
    DIRECTION OUTPUT ;
    USE SIGNAL ;
    SHAPE ABUTMENT ;
    PORT
      LAYER M4 ;
      RECT 0.000 36.960 0.024 36.984 ;
    END
  END rd_out_A[29]
  PIN rd_out_B[29]
    DIRECTION OUTPUT ;
    USE SIGNAL ;
    SHAPE ABUTMENT ;
    PORT
      LAYER M4 ;
      RECT 93.836 36.960 93.860 36.984 ;
    END
  END rd_out_B[29]
  PIN rd_out_A[30]
    DIRECTION OUTPUT ;
    USE SIGNAL ;
    SHAPE ABUTMENT ;
    PORT
      LAYER M4 ;
      RECT 0.000 37.344 0.024 37.368 ;
    END
  END rd_out_A[30]
  PIN rd_out_B[30]
    DIRECTION OUTPUT ;
    USE SIGNAL ;
    SHAPE ABUTMENT ;
    PORT
      LAYER M4 ;
      RECT 93.836 37.344 93.860 37.368 ;
    END
  END rd_out_B[30]
  PIN rd_out_A[31]
    DIRECTION OUTPUT ;
    USE SIGNAL ;
    SHAPE ABUTMENT ;
    PORT
      LAYER M4 ;
      RECT 0.000 37.728 0.024 37.752 ;
    END
  END rd_out_A[31]
  PIN rd_out_B[31]
    DIRECTION OUTPUT ;
    USE SIGNAL ;
    SHAPE ABUTMENT ;
    PORT
      LAYER M4 ;
      RECT 93.836 37.728 93.860 37.752 ;
    END
  END rd_out_B[31]
  PIN rd_out_A[32]
    DIRECTION OUTPUT ;
    USE SIGNAL ;
    SHAPE ABUTMENT ;
    PORT
      LAYER M4 ;
      RECT 0.000 38.112 0.024 38.136 ;
    END
  END rd_out_A[32]
  PIN rd_out_B[32]
    DIRECTION OUTPUT ;
    USE SIGNAL ;
    SHAPE ABUTMENT ;
    PORT
      LAYER M4 ;
      RECT 93.836 38.112 93.860 38.136 ;
    END
  END rd_out_B[32]
  PIN rd_out_A[33]
    DIRECTION OUTPUT ;
    USE SIGNAL ;
    SHAPE ABUTMENT ;
    PORT
      LAYER M4 ;
      RECT 0.000 38.496 0.024 38.520 ;
    END
  END rd_out_A[33]
  PIN rd_out_B[33]
    DIRECTION OUTPUT ;
    USE SIGNAL ;
    SHAPE ABUTMENT ;
    PORT
      LAYER M4 ;
      RECT 93.836 38.496 93.860 38.520 ;
    END
  END rd_out_B[33]
  PIN rd_out_A[34]
    DIRECTION OUTPUT ;
    USE SIGNAL ;
    SHAPE ABUTMENT ;
    PORT
      LAYER M4 ;
      RECT 0.000 38.880 0.024 38.904 ;
    END
  END rd_out_A[34]
  PIN rd_out_B[34]
    DIRECTION OUTPUT ;
    USE SIGNAL ;
    SHAPE ABUTMENT ;
    PORT
      LAYER M4 ;
      RECT 93.836 38.880 93.860 38.904 ;
    END
  END rd_out_B[34]
  PIN rd_out_A[35]
    DIRECTION OUTPUT ;
    USE SIGNAL ;
    SHAPE ABUTMENT ;
    PORT
      LAYER M4 ;
      RECT 0.000 39.264 0.024 39.288 ;
    END
  END rd_out_A[35]
  PIN rd_out_B[35]
    DIRECTION OUTPUT ;
    USE SIGNAL ;
    SHAPE ABUTMENT ;
    PORT
      LAYER M4 ;
      RECT 93.836 39.264 93.860 39.288 ;
    END
  END rd_out_B[35]
  PIN rd_out_A[36]
    DIRECTION OUTPUT ;
    USE SIGNAL ;
    SHAPE ABUTMENT ;
    PORT
      LAYER M4 ;
      RECT 0.000 39.648 0.024 39.672 ;
    END
  END rd_out_A[36]
  PIN rd_out_B[36]
    DIRECTION OUTPUT ;
    USE SIGNAL ;
    SHAPE ABUTMENT ;
    PORT
      LAYER M4 ;
      RECT 93.836 39.648 93.860 39.672 ;
    END
  END rd_out_B[36]
  PIN rd_out_A[37]
    DIRECTION OUTPUT ;
    USE SIGNAL ;
    SHAPE ABUTMENT ;
    PORT
      LAYER M4 ;
      RECT 0.000 40.032 0.024 40.056 ;
    END
  END rd_out_A[37]
  PIN rd_out_B[37]
    DIRECTION OUTPUT ;
    USE SIGNAL ;
    SHAPE ABUTMENT ;
    PORT
      LAYER M4 ;
      RECT 93.836 40.032 93.860 40.056 ;
    END
  END rd_out_B[37]
  PIN rd_out_A[38]
    DIRECTION OUTPUT ;
    USE SIGNAL ;
    SHAPE ABUTMENT ;
    PORT
      LAYER M4 ;
      RECT 0.000 40.416 0.024 40.440 ;
    END
  END rd_out_A[38]
  PIN rd_out_B[38]
    DIRECTION OUTPUT ;
    USE SIGNAL ;
    SHAPE ABUTMENT ;
    PORT
      LAYER M4 ;
      RECT 93.836 40.416 93.860 40.440 ;
    END
  END rd_out_B[38]
  PIN rd_out_A[39]
    DIRECTION OUTPUT ;
    USE SIGNAL ;
    SHAPE ABUTMENT ;
    PORT
      LAYER M4 ;
      RECT 0.000 40.800 0.024 40.824 ;
    END
  END rd_out_A[39]
  PIN rd_out_B[39]
    DIRECTION OUTPUT ;
    USE SIGNAL ;
    SHAPE ABUTMENT ;
    PORT
      LAYER M4 ;
      RECT 93.836 40.800 93.860 40.824 ;
    END
  END rd_out_B[39]
  PIN rd_out_A[40]
    DIRECTION OUTPUT ;
    USE SIGNAL ;
    SHAPE ABUTMENT ;
    PORT
      LAYER M4 ;
      RECT 0.000 41.184 0.024 41.208 ;
    END
  END rd_out_A[40]
  PIN rd_out_B[40]
    DIRECTION OUTPUT ;
    USE SIGNAL ;
    SHAPE ABUTMENT ;
    PORT
      LAYER M4 ;
      RECT 93.836 41.184 93.860 41.208 ;
    END
  END rd_out_B[40]
  PIN rd_out_A[41]
    DIRECTION OUTPUT ;
    USE SIGNAL ;
    SHAPE ABUTMENT ;
    PORT
      LAYER M4 ;
      RECT 0.000 41.568 0.024 41.592 ;
    END
  END rd_out_A[41]
  PIN rd_out_B[41]
    DIRECTION OUTPUT ;
    USE SIGNAL ;
    SHAPE ABUTMENT ;
    PORT
      LAYER M4 ;
      RECT 93.836 41.568 93.860 41.592 ;
    END
  END rd_out_B[41]
  PIN rd_out_A[42]
    DIRECTION OUTPUT ;
    USE SIGNAL ;
    SHAPE ABUTMENT ;
    PORT
      LAYER M4 ;
      RECT 0.000 41.952 0.024 41.976 ;
    END
  END rd_out_A[42]
  PIN rd_out_B[42]
    DIRECTION OUTPUT ;
    USE SIGNAL ;
    SHAPE ABUTMENT ;
    PORT
      LAYER M4 ;
      RECT 93.836 41.952 93.860 41.976 ;
    END
  END rd_out_B[42]
  PIN rd_out_A[43]
    DIRECTION OUTPUT ;
    USE SIGNAL ;
    SHAPE ABUTMENT ;
    PORT
      LAYER M4 ;
      RECT 0.000 42.336 0.024 42.360 ;
    END
  END rd_out_A[43]
  PIN rd_out_B[43]
    DIRECTION OUTPUT ;
    USE SIGNAL ;
    SHAPE ABUTMENT ;
    PORT
      LAYER M4 ;
      RECT 93.836 42.336 93.860 42.360 ;
    END
  END rd_out_B[43]
  PIN rd_out_A[44]
    DIRECTION OUTPUT ;
    USE SIGNAL ;
    SHAPE ABUTMENT ;
    PORT
      LAYER M4 ;
      RECT 0.000 42.720 0.024 42.744 ;
    END
  END rd_out_A[44]
  PIN rd_out_B[44]
    DIRECTION OUTPUT ;
    USE SIGNAL ;
    SHAPE ABUTMENT ;
    PORT
      LAYER M4 ;
      RECT 93.836 42.720 93.860 42.744 ;
    END
  END rd_out_B[44]
  PIN rd_out_A[45]
    DIRECTION OUTPUT ;
    USE SIGNAL ;
    SHAPE ABUTMENT ;
    PORT
      LAYER M4 ;
      RECT 0.000 43.104 0.024 43.128 ;
    END
  END rd_out_A[45]
  PIN rd_out_B[45]
    DIRECTION OUTPUT ;
    USE SIGNAL ;
    SHAPE ABUTMENT ;
    PORT
      LAYER M4 ;
      RECT 93.836 43.104 93.860 43.128 ;
    END
  END rd_out_B[45]
  PIN rd_out_A[46]
    DIRECTION OUTPUT ;
    USE SIGNAL ;
    SHAPE ABUTMENT ;
    PORT
      LAYER M4 ;
      RECT 0.000 43.488 0.024 43.512 ;
    END
  END rd_out_A[46]
  PIN rd_out_B[46]
    DIRECTION OUTPUT ;
    USE SIGNAL ;
    SHAPE ABUTMENT ;
    PORT
      LAYER M4 ;
      RECT 93.836 43.488 93.860 43.512 ;
    END
  END rd_out_B[46]
  PIN rd_out_A[47]
    DIRECTION OUTPUT ;
    USE SIGNAL ;
    SHAPE ABUTMENT ;
    PORT
      LAYER M4 ;
      RECT 0.000 43.872 0.024 43.896 ;
    END
  END rd_out_A[47]
  PIN rd_out_B[47]
    DIRECTION OUTPUT ;
    USE SIGNAL ;
    SHAPE ABUTMENT ;
    PORT
      LAYER M4 ;
      RECT 93.836 43.872 93.860 43.896 ;
    END
  END rd_out_B[47]
  PIN rd_out_A[48]
    DIRECTION OUTPUT ;
    USE SIGNAL ;
    SHAPE ABUTMENT ;
    PORT
      LAYER M4 ;
      RECT 0.000 44.256 0.024 44.280 ;
    END
  END rd_out_A[48]
  PIN rd_out_B[48]
    DIRECTION OUTPUT ;
    USE SIGNAL ;
    SHAPE ABUTMENT ;
    PORT
      LAYER M4 ;
      RECT 93.836 44.256 93.860 44.280 ;
    END
  END rd_out_B[48]
  PIN rd_out_A[49]
    DIRECTION OUTPUT ;
    USE SIGNAL ;
    SHAPE ABUTMENT ;
    PORT
      LAYER M4 ;
      RECT 0.000 44.640 0.024 44.664 ;
    END
  END rd_out_A[49]
  PIN rd_out_B[49]
    DIRECTION OUTPUT ;
    USE SIGNAL ;
    SHAPE ABUTMENT ;
    PORT
      LAYER M4 ;
      RECT 93.836 44.640 93.860 44.664 ;
    END
  END rd_out_B[49]
  PIN rd_out_A[50]
    DIRECTION OUTPUT ;
    USE SIGNAL ;
    SHAPE ABUTMENT ;
    PORT
      LAYER M4 ;
      RECT 0.000 45.024 0.024 45.048 ;
    END
  END rd_out_A[50]
  PIN rd_out_B[50]
    DIRECTION OUTPUT ;
    USE SIGNAL ;
    SHAPE ABUTMENT ;
    PORT
      LAYER M4 ;
      RECT 93.836 45.024 93.860 45.048 ;
    END
  END rd_out_B[50]
  PIN rd_out_A[51]
    DIRECTION OUTPUT ;
    USE SIGNAL ;
    SHAPE ABUTMENT ;
    PORT
      LAYER M4 ;
      RECT 0.000 45.408 0.024 45.432 ;
    END
  END rd_out_A[51]
  PIN rd_out_B[51]
    DIRECTION OUTPUT ;
    USE SIGNAL ;
    SHAPE ABUTMENT ;
    PORT
      LAYER M4 ;
      RECT 93.836 45.408 93.860 45.432 ;
    END
  END rd_out_B[51]
  PIN rd_out_A[52]
    DIRECTION OUTPUT ;
    USE SIGNAL ;
    SHAPE ABUTMENT ;
    PORT
      LAYER M4 ;
      RECT 0.000 45.792 0.024 45.816 ;
    END
  END rd_out_A[52]
  PIN rd_out_B[52]
    DIRECTION OUTPUT ;
    USE SIGNAL ;
    SHAPE ABUTMENT ;
    PORT
      LAYER M4 ;
      RECT 93.836 45.792 93.860 45.816 ;
    END
  END rd_out_B[52]
  PIN rd_out_A[53]
    DIRECTION OUTPUT ;
    USE SIGNAL ;
    SHAPE ABUTMENT ;
    PORT
      LAYER M4 ;
      RECT 0.000 46.176 0.024 46.200 ;
    END
  END rd_out_A[53]
  PIN rd_out_B[53]
    DIRECTION OUTPUT ;
    USE SIGNAL ;
    SHAPE ABUTMENT ;
    PORT
      LAYER M4 ;
      RECT 93.836 46.176 93.860 46.200 ;
    END
  END rd_out_B[53]
  PIN rd_out_A[54]
    DIRECTION OUTPUT ;
    USE SIGNAL ;
    SHAPE ABUTMENT ;
    PORT
      LAYER M4 ;
      RECT 0.000 46.560 0.024 46.584 ;
    END
  END rd_out_A[54]
  PIN rd_out_B[54]
    DIRECTION OUTPUT ;
    USE SIGNAL ;
    SHAPE ABUTMENT ;
    PORT
      LAYER M4 ;
      RECT 93.836 46.560 93.860 46.584 ;
    END
  END rd_out_B[54]
  PIN rd_out_A[55]
    DIRECTION OUTPUT ;
    USE SIGNAL ;
    SHAPE ABUTMENT ;
    PORT
      LAYER M4 ;
      RECT 0.000 46.944 0.024 46.968 ;
    END
  END rd_out_A[55]
  PIN rd_out_B[55]
    DIRECTION OUTPUT ;
    USE SIGNAL ;
    SHAPE ABUTMENT ;
    PORT
      LAYER M4 ;
      RECT 93.836 46.944 93.860 46.968 ;
    END
  END rd_out_B[55]
  PIN rd_out_A[56]
    DIRECTION OUTPUT ;
    USE SIGNAL ;
    SHAPE ABUTMENT ;
    PORT
      LAYER M4 ;
      RECT 0.000 47.328 0.024 47.352 ;
    END
  END rd_out_A[56]
  PIN rd_out_B[56]
    DIRECTION OUTPUT ;
    USE SIGNAL ;
    SHAPE ABUTMENT ;
    PORT
      LAYER M4 ;
      RECT 93.836 47.328 93.860 47.352 ;
    END
  END rd_out_B[56]
  PIN rd_out_A[57]
    DIRECTION OUTPUT ;
    USE SIGNAL ;
    SHAPE ABUTMENT ;
    PORT
      LAYER M4 ;
      RECT 0.000 47.712 0.024 47.736 ;
    END
  END rd_out_A[57]
  PIN rd_out_B[57]
    DIRECTION OUTPUT ;
    USE SIGNAL ;
    SHAPE ABUTMENT ;
    PORT
      LAYER M4 ;
      RECT 93.836 47.712 93.860 47.736 ;
    END
  END rd_out_B[57]
  PIN rd_out_A[58]
    DIRECTION OUTPUT ;
    USE SIGNAL ;
    SHAPE ABUTMENT ;
    PORT
      LAYER M4 ;
      RECT 0.000 48.096 0.024 48.120 ;
    END
  END rd_out_A[58]
  PIN rd_out_B[58]
    DIRECTION OUTPUT ;
    USE SIGNAL ;
    SHAPE ABUTMENT ;
    PORT
      LAYER M4 ;
      RECT 93.836 48.096 93.860 48.120 ;
    END
  END rd_out_B[58]
  PIN rd_out_A[59]
    DIRECTION OUTPUT ;
    USE SIGNAL ;
    SHAPE ABUTMENT ;
    PORT
      LAYER M4 ;
      RECT 0.000 48.480 0.024 48.504 ;
    END
  END rd_out_A[59]
  PIN rd_out_B[59]
    DIRECTION OUTPUT ;
    USE SIGNAL ;
    SHAPE ABUTMENT ;
    PORT
      LAYER M4 ;
      RECT 93.836 48.480 93.860 48.504 ;
    END
  END rd_out_B[59]
  PIN rd_out_A[60]
    DIRECTION OUTPUT ;
    USE SIGNAL ;
    SHAPE ABUTMENT ;
    PORT
      LAYER M4 ;
      RECT 0.000 48.864 0.024 48.888 ;
    END
  END rd_out_A[60]
  PIN rd_out_B[60]
    DIRECTION OUTPUT ;
    USE SIGNAL ;
    SHAPE ABUTMENT ;
    PORT
      LAYER M4 ;
      RECT 93.836 48.864 93.860 48.888 ;
    END
  END rd_out_B[60]
  PIN rd_out_A[61]
    DIRECTION OUTPUT ;
    USE SIGNAL ;
    SHAPE ABUTMENT ;
    PORT
      LAYER M4 ;
      RECT 0.000 49.248 0.024 49.272 ;
    END
  END rd_out_A[61]
  PIN rd_out_B[61]
    DIRECTION OUTPUT ;
    USE SIGNAL ;
    SHAPE ABUTMENT ;
    PORT
      LAYER M4 ;
      RECT 93.836 49.248 93.860 49.272 ;
    END
  END rd_out_B[61]
  PIN rd_out_A[62]
    DIRECTION OUTPUT ;
    USE SIGNAL ;
    SHAPE ABUTMENT ;
    PORT
      LAYER M4 ;
      RECT 0.000 49.632 0.024 49.656 ;
    END
  END rd_out_A[62]
  PIN rd_out_B[62]
    DIRECTION OUTPUT ;
    USE SIGNAL ;
    SHAPE ABUTMENT ;
    PORT
      LAYER M4 ;
      RECT 93.836 49.632 93.860 49.656 ;
    END
  END rd_out_B[62]
  PIN rd_out_A[63]
    DIRECTION OUTPUT ;
    USE SIGNAL ;
    SHAPE ABUTMENT ;
    PORT
      LAYER M4 ;
      RECT 0.000 50.016 0.024 50.040 ;
    END
  END rd_out_A[63]
  PIN rd_out_B[63]
    DIRECTION OUTPUT ;
    USE SIGNAL ;
    SHAPE ABUTMENT ;
    PORT
      LAYER M4 ;
      RECT 93.836 50.016 93.860 50.040 ;
    END
  END rd_out_B[63]
  PIN wd_in_A[0]
    DIRECTION INPUT ;
    USE SIGNAL ;
    SHAPE ABUTMENT ;
    PORT
      LAYER M4 ;
      RECT 0.000 51.600 0.024 51.624 ;
    END
  END wd_in_A[0]
  PIN wd_in_B[0]
    DIRECTION INPUT ;
    USE SIGNAL ;
    SHAPE ABUTMENT ;
    PORT
      LAYER M4 ;
      RECT 93.836 51.600 93.860 51.624 ;
    END
  END wd_in_B[0]
  PIN wd_in_A[1]
    DIRECTION INPUT ;
    USE SIGNAL ;
    SHAPE ABUTMENT ;
    PORT
      LAYER M4 ;
      RECT 0.000 51.984 0.024 52.008 ;
    END
  END wd_in_A[1]
  PIN wd_in_B[1]
    DIRECTION INPUT ;
    USE SIGNAL ;
    SHAPE ABUTMENT ;
    PORT
      LAYER M4 ;
      RECT 93.836 51.984 93.860 52.008 ;
    END
  END wd_in_B[1]
  PIN wd_in_A[2]
    DIRECTION INPUT ;
    USE SIGNAL ;
    SHAPE ABUTMENT ;
    PORT
      LAYER M4 ;
      RECT 0.000 52.368 0.024 52.392 ;
    END
  END wd_in_A[2]
  PIN wd_in_B[2]
    DIRECTION INPUT ;
    USE SIGNAL ;
    SHAPE ABUTMENT ;
    PORT
      LAYER M4 ;
      RECT 93.836 52.368 93.860 52.392 ;
    END
  END wd_in_B[2]
  PIN wd_in_A[3]
    DIRECTION INPUT ;
    USE SIGNAL ;
    SHAPE ABUTMENT ;
    PORT
      LAYER M4 ;
      RECT 0.000 52.752 0.024 52.776 ;
    END
  END wd_in_A[3]
  PIN wd_in_B[3]
    DIRECTION INPUT ;
    USE SIGNAL ;
    SHAPE ABUTMENT ;
    PORT
      LAYER M4 ;
      RECT 93.836 52.752 93.860 52.776 ;
    END
  END wd_in_B[3]
  PIN wd_in_A[4]
    DIRECTION INPUT ;
    USE SIGNAL ;
    SHAPE ABUTMENT ;
    PORT
      LAYER M4 ;
      RECT 0.000 53.136 0.024 53.160 ;
    END
  END wd_in_A[4]
  PIN wd_in_B[4]
    DIRECTION INPUT ;
    USE SIGNAL ;
    SHAPE ABUTMENT ;
    PORT
      LAYER M4 ;
      RECT 93.836 53.136 93.860 53.160 ;
    END
  END wd_in_B[4]
  PIN wd_in_A[5]
    DIRECTION INPUT ;
    USE SIGNAL ;
    SHAPE ABUTMENT ;
    PORT
      LAYER M4 ;
      RECT 0.000 53.520 0.024 53.544 ;
    END
  END wd_in_A[5]
  PIN wd_in_B[5]
    DIRECTION INPUT ;
    USE SIGNAL ;
    SHAPE ABUTMENT ;
    PORT
      LAYER M4 ;
      RECT 93.836 53.520 93.860 53.544 ;
    END
  END wd_in_B[5]
  PIN wd_in_A[6]
    DIRECTION INPUT ;
    USE SIGNAL ;
    SHAPE ABUTMENT ;
    PORT
      LAYER M4 ;
      RECT 0.000 53.904 0.024 53.928 ;
    END
  END wd_in_A[6]
  PIN wd_in_B[6]
    DIRECTION INPUT ;
    USE SIGNAL ;
    SHAPE ABUTMENT ;
    PORT
      LAYER M4 ;
      RECT 93.836 53.904 93.860 53.928 ;
    END
  END wd_in_B[6]
  PIN wd_in_A[7]
    DIRECTION INPUT ;
    USE SIGNAL ;
    SHAPE ABUTMENT ;
    PORT
      LAYER M4 ;
      RECT 0.000 54.288 0.024 54.312 ;
    END
  END wd_in_A[7]
  PIN wd_in_B[7]
    DIRECTION INPUT ;
    USE SIGNAL ;
    SHAPE ABUTMENT ;
    PORT
      LAYER M4 ;
      RECT 93.836 54.288 93.860 54.312 ;
    END
  END wd_in_B[7]
  PIN wd_in_A[8]
    DIRECTION INPUT ;
    USE SIGNAL ;
    SHAPE ABUTMENT ;
    PORT
      LAYER M4 ;
      RECT 0.000 54.672 0.024 54.696 ;
    END
  END wd_in_A[8]
  PIN wd_in_B[8]
    DIRECTION INPUT ;
    USE SIGNAL ;
    SHAPE ABUTMENT ;
    PORT
      LAYER M4 ;
      RECT 93.836 54.672 93.860 54.696 ;
    END
  END wd_in_B[8]
  PIN wd_in_A[9]
    DIRECTION INPUT ;
    USE SIGNAL ;
    SHAPE ABUTMENT ;
    PORT
      LAYER M4 ;
      RECT 0.000 55.056 0.024 55.080 ;
    END
  END wd_in_A[9]
  PIN wd_in_B[9]
    DIRECTION INPUT ;
    USE SIGNAL ;
    SHAPE ABUTMENT ;
    PORT
      LAYER M4 ;
      RECT 93.836 55.056 93.860 55.080 ;
    END
  END wd_in_B[9]
  PIN wd_in_A[10]
    DIRECTION INPUT ;
    USE SIGNAL ;
    SHAPE ABUTMENT ;
    PORT
      LAYER M4 ;
      RECT 0.000 55.440 0.024 55.464 ;
    END
  END wd_in_A[10]
  PIN wd_in_B[10]
    DIRECTION INPUT ;
    USE SIGNAL ;
    SHAPE ABUTMENT ;
    PORT
      LAYER M4 ;
      RECT 93.836 55.440 93.860 55.464 ;
    END
  END wd_in_B[10]
  PIN wd_in_A[11]
    DIRECTION INPUT ;
    USE SIGNAL ;
    SHAPE ABUTMENT ;
    PORT
      LAYER M4 ;
      RECT 0.000 55.824 0.024 55.848 ;
    END
  END wd_in_A[11]
  PIN wd_in_B[11]
    DIRECTION INPUT ;
    USE SIGNAL ;
    SHAPE ABUTMENT ;
    PORT
      LAYER M4 ;
      RECT 93.836 55.824 93.860 55.848 ;
    END
  END wd_in_B[11]
  PIN wd_in_A[12]
    DIRECTION INPUT ;
    USE SIGNAL ;
    SHAPE ABUTMENT ;
    PORT
      LAYER M4 ;
      RECT 0.000 56.208 0.024 56.232 ;
    END
  END wd_in_A[12]
  PIN wd_in_B[12]
    DIRECTION INPUT ;
    USE SIGNAL ;
    SHAPE ABUTMENT ;
    PORT
      LAYER M4 ;
      RECT 93.836 56.208 93.860 56.232 ;
    END
  END wd_in_B[12]
  PIN wd_in_A[13]
    DIRECTION INPUT ;
    USE SIGNAL ;
    SHAPE ABUTMENT ;
    PORT
      LAYER M4 ;
      RECT 0.000 56.592 0.024 56.616 ;
    END
  END wd_in_A[13]
  PIN wd_in_B[13]
    DIRECTION INPUT ;
    USE SIGNAL ;
    SHAPE ABUTMENT ;
    PORT
      LAYER M4 ;
      RECT 93.836 56.592 93.860 56.616 ;
    END
  END wd_in_B[13]
  PIN wd_in_A[14]
    DIRECTION INPUT ;
    USE SIGNAL ;
    SHAPE ABUTMENT ;
    PORT
      LAYER M4 ;
      RECT 0.000 56.976 0.024 57.000 ;
    END
  END wd_in_A[14]
  PIN wd_in_B[14]
    DIRECTION INPUT ;
    USE SIGNAL ;
    SHAPE ABUTMENT ;
    PORT
      LAYER M4 ;
      RECT 93.836 56.976 93.860 57.000 ;
    END
  END wd_in_B[14]
  PIN wd_in_A[15]
    DIRECTION INPUT ;
    USE SIGNAL ;
    SHAPE ABUTMENT ;
    PORT
      LAYER M4 ;
      RECT 0.000 57.360 0.024 57.384 ;
    END
  END wd_in_A[15]
  PIN wd_in_B[15]
    DIRECTION INPUT ;
    USE SIGNAL ;
    SHAPE ABUTMENT ;
    PORT
      LAYER M4 ;
      RECT 93.836 57.360 93.860 57.384 ;
    END
  END wd_in_B[15]
  PIN wd_in_A[16]
    DIRECTION INPUT ;
    USE SIGNAL ;
    SHAPE ABUTMENT ;
    PORT
      LAYER M4 ;
      RECT 0.000 57.744 0.024 57.768 ;
    END
  END wd_in_A[16]
  PIN wd_in_B[16]
    DIRECTION INPUT ;
    USE SIGNAL ;
    SHAPE ABUTMENT ;
    PORT
      LAYER M4 ;
      RECT 93.836 57.744 93.860 57.768 ;
    END
  END wd_in_B[16]
  PIN wd_in_A[17]
    DIRECTION INPUT ;
    USE SIGNAL ;
    SHAPE ABUTMENT ;
    PORT
      LAYER M4 ;
      RECT 0.000 58.128 0.024 58.152 ;
    END
  END wd_in_A[17]
  PIN wd_in_B[17]
    DIRECTION INPUT ;
    USE SIGNAL ;
    SHAPE ABUTMENT ;
    PORT
      LAYER M4 ;
      RECT 93.836 58.128 93.860 58.152 ;
    END
  END wd_in_B[17]
  PIN wd_in_A[18]
    DIRECTION INPUT ;
    USE SIGNAL ;
    SHAPE ABUTMENT ;
    PORT
      LAYER M4 ;
      RECT 0.000 58.512 0.024 58.536 ;
    END
  END wd_in_A[18]
  PIN wd_in_B[18]
    DIRECTION INPUT ;
    USE SIGNAL ;
    SHAPE ABUTMENT ;
    PORT
      LAYER M4 ;
      RECT 93.836 58.512 93.860 58.536 ;
    END
  END wd_in_B[18]
  PIN wd_in_A[19]
    DIRECTION INPUT ;
    USE SIGNAL ;
    SHAPE ABUTMENT ;
    PORT
      LAYER M4 ;
      RECT 0.000 58.896 0.024 58.920 ;
    END
  END wd_in_A[19]
  PIN wd_in_B[19]
    DIRECTION INPUT ;
    USE SIGNAL ;
    SHAPE ABUTMENT ;
    PORT
      LAYER M4 ;
      RECT 93.836 58.896 93.860 58.920 ;
    END
  END wd_in_B[19]
  PIN wd_in_A[20]
    DIRECTION INPUT ;
    USE SIGNAL ;
    SHAPE ABUTMENT ;
    PORT
      LAYER M4 ;
      RECT 0.000 59.280 0.024 59.304 ;
    END
  END wd_in_A[20]
  PIN wd_in_B[20]
    DIRECTION INPUT ;
    USE SIGNAL ;
    SHAPE ABUTMENT ;
    PORT
      LAYER M4 ;
      RECT 93.836 59.280 93.860 59.304 ;
    END
  END wd_in_B[20]
  PIN wd_in_A[21]
    DIRECTION INPUT ;
    USE SIGNAL ;
    SHAPE ABUTMENT ;
    PORT
      LAYER M4 ;
      RECT 0.000 59.664 0.024 59.688 ;
    END
  END wd_in_A[21]
  PIN wd_in_B[21]
    DIRECTION INPUT ;
    USE SIGNAL ;
    SHAPE ABUTMENT ;
    PORT
      LAYER M4 ;
      RECT 93.836 59.664 93.860 59.688 ;
    END
  END wd_in_B[21]
  PIN wd_in_A[22]
    DIRECTION INPUT ;
    USE SIGNAL ;
    SHAPE ABUTMENT ;
    PORT
      LAYER M4 ;
      RECT 0.000 60.048 0.024 60.072 ;
    END
  END wd_in_A[22]
  PIN wd_in_B[22]
    DIRECTION INPUT ;
    USE SIGNAL ;
    SHAPE ABUTMENT ;
    PORT
      LAYER M4 ;
      RECT 93.836 60.048 93.860 60.072 ;
    END
  END wd_in_B[22]
  PIN wd_in_A[23]
    DIRECTION INPUT ;
    USE SIGNAL ;
    SHAPE ABUTMENT ;
    PORT
      LAYER M4 ;
      RECT 0.000 60.432 0.024 60.456 ;
    END
  END wd_in_A[23]
  PIN wd_in_B[23]
    DIRECTION INPUT ;
    USE SIGNAL ;
    SHAPE ABUTMENT ;
    PORT
      LAYER M4 ;
      RECT 93.836 60.432 93.860 60.456 ;
    END
  END wd_in_B[23]
  PIN wd_in_A[24]
    DIRECTION INPUT ;
    USE SIGNAL ;
    SHAPE ABUTMENT ;
    PORT
      LAYER M4 ;
      RECT 0.000 60.816 0.024 60.840 ;
    END
  END wd_in_A[24]
  PIN wd_in_B[24]
    DIRECTION INPUT ;
    USE SIGNAL ;
    SHAPE ABUTMENT ;
    PORT
      LAYER M4 ;
      RECT 93.836 60.816 93.860 60.840 ;
    END
  END wd_in_B[24]
  PIN wd_in_A[25]
    DIRECTION INPUT ;
    USE SIGNAL ;
    SHAPE ABUTMENT ;
    PORT
      LAYER M4 ;
      RECT 0.000 61.200 0.024 61.224 ;
    END
  END wd_in_A[25]
  PIN wd_in_B[25]
    DIRECTION INPUT ;
    USE SIGNAL ;
    SHAPE ABUTMENT ;
    PORT
      LAYER M4 ;
      RECT 93.836 61.200 93.860 61.224 ;
    END
  END wd_in_B[25]
  PIN wd_in_A[26]
    DIRECTION INPUT ;
    USE SIGNAL ;
    SHAPE ABUTMENT ;
    PORT
      LAYER M4 ;
      RECT 0.000 61.584 0.024 61.608 ;
    END
  END wd_in_A[26]
  PIN wd_in_B[26]
    DIRECTION INPUT ;
    USE SIGNAL ;
    SHAPE ABUTMENT ;
    PORT
      LAYER M4 ;
      RECT 93.836 61.584 93.860 61.608 ;
    END
  END wd_in_B[26]
  PIN wd_in_A[27]
    DIRECTION INPUT ;
    USE SIGNAL ;
    SHAPE ABUTMENT ;
    PORT
      LAYER M4 ;
      RECT 0.000 61.968 0.024 61.992 ;
    END
  END wd_in_A[27]
  PIN wd_in_B[27]
    DIRECTION INPUT ;
    USE SIGNAL ;
    SHAPE ABUTMENT ;
    PORT
      LAYER M4 ;
      RECT 93.836 61.968 93.860 61.992 ;
    END
  END wd_in_B[27]
  PIN wd_in_A[28]
    DIRECTION INPUT ;
    USE SIGNAL ;
    SHAPE ABUTMENT ;
    PORT
      LAYER M4 ;
      RECT 0.000 62.352 0.024 62.376 ;
    END
  END wd_in_A[28]
  PIN wd_in_B[28]
    DIRECTION INPUT ;
    USE SIGNAL ;
    SHAPE ABUTMENT ;
    PORT
      LAYER M4 ;
      RECT 93.836 62.352 93.860 62.376 ;
    END
  END wd_in_B[28]
  PIN wd_in_A[29]
    DIRECTION INPUT ;
    USE SIGNAL ;
    SHAPE ABUTMENT ;
    PORT
      LAYER M4 ;
      RECT 0.000 62.736 0.024 62.760 ;
    END
  END wd_in_A[29]
  PIN wd_in_B[29]
    DIRECTION INPUT ;
    USE SIGNAL ;
    SHAPE ABUTMENT ;
    PORT
      LAYER M4 ;
      RECT 93.836 62.736 93.860 62.760 ;
    END
  END wd_in_B[29]
  PIN wd_in_A[30]
    DIRECTION INPUT ;
    USE SIGNAL ;
    SHAPE ABUTMENT ;
    PORT
      LAYER M4 ;
      RECT 0.000 63.120 0.024 63.144 ;
    END
  END wd_in_A[30]
  PIN wd_in_B[30]
    DIRECTION INPUT ;
    USE SIGNAL ;
    SHAPE ABUTMENT ;
    PORT
      LAYER M4 ;
      RECT 93.836 63.120 93.860 63.144 ;
    END
  END wd_in_B[30]
  PIN wd_in_A[31]
    DIRECTION INPUT ;
    USE SIGNAL ;
    SHAPE ABUTMENT ;
    PORT
      LAYER M4 ;
      RECT 0.000 63.504 0.024 63.528 ;
    END
  END wd_in_A[31]
  PIN wd_in_B[31]
    DIRECTION INPUT ;
    USE SIGNAL ;
    SHAPE ABUTMENT ;
    PORT
      LAYER M4 ;
      RECT 93.836 63.504 93.860 63.528 ;
    END
  END wd_in_B[31]
  PIN wd_in_A[32]
    DIRECTION INPUT ;
    USE SIGNAL ;
    SHAPE ABUTMENT ;
    PORT
      LAYER M4 ;
      RECT 0.000 63.888 0.024 63.912 ;
    END
  END wd_in_A[32]
  PIN wd_in_B[32]
    DIRECTION INPUT ;
    USE SIGNAL ;
    SHAPE ABUTMENT ;
    PORT
      LAYER M4 ;
      RECT 93.836 63.888 93.860 63.912 ;
    END
  END wd_in_B[32]
  PIN wd_in_A[33]
    DIRECTION INPUT ;
    USE SIGNAL ;
    SHAPE ABUTMENT ;
    PORT
      LAYER M4 ;
      RECT 0.000 64.272 0.024 64.296 ;
    END
  END wd_in_A[33]
  PIN wd_in_B[33]
    DIRECTION INPUT ;
    USE SIGNAL ;
    SHAPE ABUTMENT ;
    PORT
      LAYER M4 ;
      RECT 93.836 64.272 93.860 64.296 ;
    END
  END wd_in_B[33]
  PIN wd_in_A[34]
    DIRECTION INPUT ;
    USE SIGNAL ;
    SHAPE ABUTMENT ;
    PORT
      LAYER M4 ;
      RECT 0.000 64.656 0.024 64.680 ;
    END
  END wd_in_A[34]
  PIN wd_in_B[34]
    DIRECTION INPUT ;
    USE SIGNAL ;
    SHAPE ABUTMENT ;
    PORT
      LAYER M4 ;
      RECT 93.836 64.656 93.860 64.680 ;
    END
  END wd_in_B[34]
  PIN wd_in_A[35]
    DIRECTION INPUT ;
    USE SIGNAL ;
    SHAPE ABUTMENT ;
    PORT
      LAYER M4 ;
      RECT 0.000 65.040 0.024 65.064 ;
    END
  END wd_in_A[35]
  PIN wd_in_B[35]
    DIRECTION INPUT ;
    USE SIGNAL ;
    SHAPE ABUTMENT ;
    PORT
      LAYER M4 ;
      RECT 93.836 65.040 93.860 65.064 ;
    END
  END wd_in_B[35]
  PIN wd_in_A[36]
    DIRECTION INPUT ;
    USE SIGNAL ;
    SHAPE ABUTMENT ;
    PORT
      LAYER M4 ;
      RECT 0.000 65.424 0.024 65.448 ;
    END
  END wd_in_A[36]
  PIN wd_in_B[36]
    DIRECTION INPUT ;
    USE SIGNAL ;
    SHAPE ABUTMENT ;
    PORT
      LAYER M4 ;
      RECT 93.836 65.424 93.860 65.448 ;
    END
  END wd_in_B[36]
  PIN wd_in_A[37]
    DIRECTION INPUT ;
    USE SIGNAL ;
    SHAPE ABUTMENT ;
    PORT
      LAYER M4 ;
      RECT 0.000 65.808 0.024 65.832 ;
    END
  END wd_in_A[37]
  PIN wd_in_B[37]
    DIRECTION INPUT ;
    USE SIGNAL ;
    SHAPE ABUTMENT ;
    PORT
      LAYER M4 ;
      RECT 93.836 65.808 93.860 65.832 ;
    END
  END wd_in_B[37]
  PIN wd_in_A[38]
    DIRECTION INPUT ;
    USE SIGNAL ;
    SHAPE ABUTMENT ;
    PORT
      LAYER M4 ;
      RECT 0.000 66.192 0.024 66.216 ;
    END
  END wd_in_A[38]
  PIN wd_in_B[38]
    DIRECTION INPUT ;
    USE SIGNAL ;
    SHAPE ABUTMENT ;
    PORT
      LAYER M4 ;
      RECT 93.836 66.192 93.860 66.216 ;
    END
  END wd_in_B[38]
  PIN wd_in_A[39]
    DIRECTION INPUT ;
    USE SIGNAL ;
    SHAPE ABUTMENT ;
    PORT
      LAYER M4 ;
      RECT 0.000 66.576 0.024 66.600 ;
    END
  END wd_in_A[39]
  PIN wd_in_B[39]
    DIRECTION INPUT ;
    USE SIGNAL ;
    SHAPE ABUTMENT ;
    PORT
      LAYER M4 ;
      RECT 93.836 66.576 93.860 66.600 ;
    END
  END wd_in_B[39]
  PIN wd_in_A[40]
    DIRECTION INPUT ;
    USE SIGNAL ;
    SHAPE ABUTMENT ;
    PORT
      LAYER M4 ;
      RECT 0.000 66.960 0.024 66.984 ;
    END
  END wd_in_A[40]
  PIN wd_in_B[40]
    DIRECTION INPUT ;
    USE SIGNAL ;
    SHAPE ABUTMENT ;
    PORT
      LAYER M4 ;
      RECT 93.836 66.960 93.860 66.984 ;
    END
  END wd_in_B[40]
  PIN wd_in_A[41]
    DIRECTION INPUT ;
    USE SIGNAL ;
    SHAPE ABUTMENT ;
    PORT
      LAYER M4 ;
      RECT 0.000 67.344 0.024 67.368 ;
    END
  END wd_in_A[41]
  PIN wd_in_B[41]
    DIRECTION INPUT ;
    USE SIGNAL ;
    SHAPE ABUTMENT ;
    PORT
      LAYER M4 ;
      RECT 93.836 67.344 93.860 67.368 ;
    END
  END wd_in_B[41]
  PIN wd_in_A[42]
    DIRECTION INPUT ;
    USE SIGNAL ;
    SHAPE ABUTMENT ;
    PORT
      LAYER M4 ;
      RECT 0.000 67.728 0.024 67.752 ;
    END
  END wd_in_A[42]
  PIN wd_in_B[42]
    DIRECTION INPUT ;
    USE SIGNAL ;
    SHAPE ABUTMENT ;
    PORT
      LAYER M4 ;
      RECT 93.836 67.728 93.860 67.752 ;
    END
  END wd_in_B[42]
  PIN wd_in_A[43]
    DIRECTION INPUT ;
    USE SIGNAL ;
    SHAPE ABUTMENT ;
    PORT
      LAYER M4 ;
      RECT 0.000 68.112 0.024 68.136 ;
    END
  END wd_in_A[43]
  PIN wd_in_B[43]
    DIRECTION INPUT ;
    USE SIGNAL ;
    SHAPE ABUTMENT ;
    PORT
      LAYER M4 ;
      RECT 93.836 68.112 93.860 68.136 ;
    END
  END wd_in_B[43]
  PIN wd_in_A[44]
    DIRECTION INPUT ;
    USE SIGNAL ;
    SHAPE ABUTMENT ;
    PORT
      LAYER M4 ;
      RECT 0.000 68.496 0.024 68.520 ;
    END
  END wd_in_A[44]
  PIN wd_in_B[44]
    DIRECTION INPUT ;
    USE SIGNAL ;
    SHAPE ABUTMENT ;
    PORT
      LAYER M4 ;
      RECT 93.836 68.496 93.860 68.520 ;
    END
  END wd_in_B[44]
  PIN wd_in_A[45]
    DIRECTION INPUT ;
    USE SIGNAL ;
    SHAPE ABUTMENT ;
    PORT
      LAYER M4 ;
      RECT 0.000 68.880 0.024 68.904 ;
    END
  END wd_in_A[45]
  PIN wd_in_B[45]
    DIRECTION INPUT ;
    USE SIGNAL ;
    SHAPE ABUTMENT ;
    PORT
      LAYER M4 ;
      RECT 93.836 68.880 93.860 68.904 ;
    END
  END wd_in_B[45]
  PIN wd_in_A[46]
    DIRECTION INPUT ;
    USE SIGNAL ;
    SHAPE ABUTMENT ;
    PORT
      LAYER M4 ;
      RECT 0.000 69.264 0.024 69.288 ;
    END
  END wd_in_A[46]
  PIN wd_in_B[46]
    DIRECTION INPUT ;
    USE SIGNAL ;
    SHAPE ABUTMENT ;
    PORT
      LAYER M4 ;
      RECT 93.836 69.264 93.860 69.288 ;
    END
  END wd_in_B[46]
  PIN wd_in_A[47]
    DIRECTION INPUT ;
    USE SIGNAL ;
    SHAPE ABUTMENT ;
    PORT
      LAYER M4 ;
      RECT 0.000 69.648 0.024 69.672 ;
    END
  END wd_in_A[47]
  PIN wd_in_B[47]
    DIRECTION INPUT ;
    USE SIGNAL ;
    SHAPE ABUTMENT ;
    PORT
      LAYER M4 ;
      RECT 93.836 69.648 93.860 69.672 ;
    END
  END wd_in_B[47]
  PIN wd_in_A[48]
    DIRECTION INPUT ;
    USE SIGNAL ;
    SHAPE ABUTMENT ;
    PORT
      LAYER M4 ;
      RECT 0.000 70.032 0.024 70.056 ;
    END
  END wd_in_A[48]
  PIN wd_in_B[48]
    DIRECTION INPUT ;
    USE SIGNAL ;
    SHAPE ABUTMENT ;
    PORT
      LAYER M4 ;
      RECT 93.836 70.032 93.860 70.056 ;
    END
  END wd_in_B[48]
  PIN wd_in_A[49]
    DIRECTION INPUT ;
    USE SIGNAL ;
    SHAPE ABUTMENT ;
    PORT
      LAYER M4 ;
      RECT 0.000 70.416 0.024 70.440 ;
    END
  END wd_in_A[49]
  PIN wd_in_B[49]
    DIRECTION INPUT ;
    USE SIGNAL ;
    SHAPE ABUTMENT ;
    PORT
      LAYER M4 ;
      RECT 93.836 70.416 93.860 70.440 ;
    END
  END wd_in_B[49]
  PIN wd_in_A[50]
    DIRECTION INPUT ;
    USE SIGNAL ;
    SHAPE ABUTMENT ;
    PORT
      LAYER M4 ;
      RECT 0.000 70.800 0.024 70.824 ;
    END
  END wd_in_A[50]
  PIN wd_in_B[50]
    DIRECTION INPUT ;
    USE SIGNAL ;
    SHAPE ABUTMENT ;
    PORT
      LAYER M4 ;
      RECT 93.836 70.800 93.860 70.824 ;
    END
  END wd_in_B[50]
  PIN wd_in_A[51]
    DIRECTION INPUT ;
    USE SIGNAL ;
    SHAPE ABUTMENT ;
    PORT
      LAYER M4 ;
      RECT 0.000 71.184 0.024 71.208 ;
    END
  END wd_in_A[51]
  PIN wd_in_B[51]
    DIRECTION INPUT ;
    USE SIGNAL ;
    SHAPE ABUTMENT ;
    PORT
      LAYER M4 ;
      RECT 93.836 71.184 93.860 71.208 ;
    END
  END wd_in_B[51]
  PIN wd_in_A[52]
    DIRECTION INPUT ;
    USE SIGNAL ;
    SHAPE ABUTMENT ;
    PORT
      LAYER M4 ;
      RECT 0.000 71.568 0.024 71.592 ;
    END
  END wd_in_A[52]
  PIN wd_in_B[52]
    DIRECTION INPUT ;
    USE SIGNAL ;
    SHAPE ABUTMENT ;
    PORT
      LAYER M4 ;
      RECT 93.836 71.568 93.860 71.592 ;
    END
  END wd_in_B[52]
  PIN wd_in_A[53]
    DIRECTION INPUT ;
    USE SIGNAL ;
    SHAPE ABUTMENT ;
    PORT
      LAYER M4 ;
      RECT 0.000 71.952 0.024 71.976 ;
    END
  END wd_in_A[53]
  PIN wd_in_B[53]
    DIRECTION INPUT ;
    USE SIGNAL ;
    SHAPE ABUTMENT ;
    PORT
      LAYER M4 ;
      RECT 93.836 71.952 93.860 71.976 ;
    END
  END wd_in_B[53]
  PIN wd_in_A[54]
    DIRECTION INPUT ;
    USE SIGNAL ;
    SHAPE ABUTMENT ;
    PORT
      LAYER M4 ;
      RECT 0.000 72.336 0.024 72.360 ;
    END
  END wd_in_A[54]
  PIN wd_in_B[54]
    DIRECTION INPUT ;
    USE SIGNAL ;
    SHAPE ABUTMENT ;
    PORT
      LAYER M4 ;
      RECT 93.836 72.336 93.860 72.360 ;
    END
  END wd_in_B[54]
  PIN wd_in_A[55]
    DIRECTION INPUT ;
    USE SIGNAL ;
    SHAPE ABUTMENT ;
    PORT
      LAYER M4 ;
      RECT 0.000 72.720 0.024 72.744 ;
    END
  END wd_in_A[55]
  PIN wd_in_B[55]
    DIRECTION INPUT ;
    USE SIGNAL ;
    SHAPE ABUTMENT ;
    PORT
      LAYER M4 ;
      RECT 93.836 72.720 93.860 72.744 ;
    END
  END wd_in_B[55]
  PIN wd_in_A[56]
    DIRECTION INPUT ;
    USE SIGNAL ;
    SHAPE ABUTMENT ;
    PORT
      LAYER M4 ;
      RECT 0.000 73.104 0.024 73.128 ;
    END
  END wd_in_A[56]
  PIN wd_in_B[56]
    DIRECTION INPUT ;
    USE SIGNAL ;
    SHAPE ABUTMENT ;
    PORT
      LAYER M4 ;
      RECT 93.836 73.104 93.860 73.128 ;
    END
  END wd_in_B[56]
  PIN wd_in_A[57]
    DIRECTION INPUT ;
    USE SIGNAL ;
    SHAPE ABUTMENT ;
    PORT
      LAYER M4 ;
      RECT 0.000 73.488 0.024 73.512 ;
    END
  END wd_in_A[57]
  PIN wd_in_B[57]
    DIRECTION INPUT ;
    USE SIGNAL ;
    SHAPE ABUTMENT ;
    PORT
      LAYER M4 ;
      RECT 93.836 73.488 93.860 73.512 ;
    END
  END wd_in_B[57]
  PIN wd_in_A[58]
    DIRECTION INPUT ;
    USE SIGNAL ;
    SHAPE ABUTMENT ;
    PORT
      LAYER M4 ;
      RECT 0.000 73.872 0.024 73.896 ;
    END
  END wd_in_A[58]
  PIN wd_in_B[58]
    DIRECTION INPUT ;
    USE SIGNAL ;
    SHAPE ABUTMENT ;
    PORT
      LAYER M4 ;
      RECT 93.836 73.872 93.860 73.896 ;
    END
  END wd_in_B[58]
  PIN wd_in_A[59]
    DIRECTION INPUT ;
    USE SIGNAL ;
    SHAPE ABUTMENT ;
    PORT
      LAYER M4 ;
      RECT 0.000 74.256 0.024 74.280 ;
    END
  END wd_in_A[59]
  PIN wd_in_B[59]
    DIRECTION INPUT ;
    USE SIGNAL ;
    SHAPE ABUTMENT ;
    PORT
      LAYER M4 ;
      RECT 93.836 74.256 93.860 74.280 ;
    END
  END wd_in_B[59]
  PIN wd_in_A[60]
    DIRECTION INPUT ;
    USE SIGNAL ;
    SHAPE ABUTMENT ;
    PORT
      LAYER M4 ;
      RECT 0.000 74.640 0.024 74.664 ;
    END
  END wd_in_A[60]
  PIN wd_in_B[60]
    DIRECTION INPUT ;
    USE SIGNAL ;
    SHAPE ABUTMENT ;
    PORT
      LAYER M4 ;
      RECT 93.836 74.640 93.860 74.664 ;
    END
  END wd_in_B[60]
  PIN wd_in_A[61]
    DIRECTION INPUT ;
    USE SIGNAL ;
    SHAPE ABUTMENT ;
    PORT
      LAYER M4 ;
      RECT 0.000 75.024 0.024 75.048 ;
    END
  END wd_in_A[61]
  PIN wd_in_B[61]
    DIRECTION INPUT ;
    USE SIGNAL ;
    SHAPE ABUTMENT ;
    PORT
      LAYER M4 ;
      RECT 93.836 75.024 93.860 75.048 ;
    END
  END wd_in_B[61]
  PIN wd_in_A[62]
    DIRECTION INPUT ;
    USE SIGNAL ;
    SHAPE ABUTMENT ;
    PORT
      LAYER M4 ;
      RECT 0.000 75.408 0.024 75.432 ;
    END
  END wd_in_A[62]
  PIN wd_in_B[62]
    DIRECTION INPUT ;
    USE SIGNAL ;
    SHAPE ABUTMENT ;
    PORT
      LAYER M4 ;
      RECT 93.836 75.408 93.860 75.432 ;
    END
  END wd_in_B[62]
  PIN wd_in_A[63]
    DIRECTION INPUT ;
    USE SIGNAL ;
    SHAPE ABUTMENT ;
    PORT
      LAYER M4 ;
      RECT 0.000 75.792 0.024 75.816 ;
    END
  END wd_in_A[63]
  PIN wd_in_B[63]
    DIRECTION INPUT ;
    USE SIGNAL ;
    SHAPE ABUTMENT ;
    PORT
      LAYER M4 ;
      RECT 93.836 75.792 93.860 75.816 ;
    END
  END wd_in_B[63]
  PIN addr_in_A[0]
    DIRECTION INPUT ;
    USE SIGNAL ;
    SHAPE ABUTMENT ;
    PORT
      LAYER M4 ;
      RECT 0.000 77.376 0.024 77.400 ;
    END
  END addr_in_A[0]
  PIN addr_in_B[0]
    DIRECTION INPUT ;
    USE SIGNAL ;
    SHAPE ABUTMENT ;
    PORT
      LAYER M4 ;
      RECT 93.836 77.376 93.860 77.400 ;
    END
  END addr_in_B[0]
  PIN addr_in_A[1]
    DIRECTION INPUT ;
    USE SIGNAL ;
    SHAPE ABUTMENT ;
    PORT
      LAYER M4 ;
      RECT 0.000 77.760 0.024 77.784 ;
    END
  END addr_in_A[1]
  PIN addr_in_B[1]
    DIRECTION INPUT ;
    USE SIGNAL ;
    SHAPE ABUTMENT ;
    PORT
      LAYER M4 ;
      RECT 93.836 77.760 93.860 77.784 ;
    END
  END addr_in_B[1]
  PIN addr_in_A[2]
    DIRECTION INPUT ;
    USE SIGNAL ;
    SHAPE ABUTMENT ;
    PORT
      LAYER M4 ;
      RECT 0.000 78.144 0.024 78.168 ;
    END
  END addr_in_A[2]
  PIN addr_in_B[2]
    DIRECTION INPUT ;
    USE SIGNAL ;
    SHAPE ABUTMENT ;
    PORT
      LAYER M4 ;
      RECT 93.836 78.144 93.860 78.168 ;
    END
  END addr_in_B[2]
  PIN addr_in_A[3]
    DIRECTION INPUT ;
    USE SIGNAL ;
    SHAPE ABUTMENT ;
    PORT
      LAYER M4 ;
      RECT 0.000 78.528 0.024 78.552 ;
    END
  END addr_in_A[3]
  PIN addr_in_B[3]
    DIRECTION INPUT ;
    USE SIGNAL ;
    SHAPE ABUTMENT ;
    PORT
      LAYER M4 ;
      RECT 93.836 78.528 93.860 78.552 ;
    END
  END addr_in_B[3]
  PIN addr_in_A[4]
    DIRECTION INPUT ;
    USE SIGNAL ;
    SHAPE ABUTMENT ;
    PORT
      LAYER M4 ;
      RECT 0.000 78.912 0.024 78.936 ;
    END
  END addr_in_A[4]
  PIN addr_in_B[4]
    DIRECTION INPUT ;
    USE SIGNAL ;
    SHAPE ABUTMENT ;
    PORT
      LAYER M4 ;
      RECT 93.836 78.912 93.860 78.936 ;
    END
  END addr_in_B[4]
  PIN addr_in_A[5]
    DIRECTION INPUT ;
    USE SIGNAL ;
    SHAPE ABUTMENT ;
    PORT
      LAYER M4 ;
      RECT 0.000 79.296 0.024 79.320 ;
    END
  END addr_in_A[5]
  PIN addr_in_B[5]
    DIRECTION INPUT ;
    USE SIGNAL ;
    SHAPE ABUTMENT ;
    PORT
      LAYER M4 ;
      RECT 93.836 79.296 93.860 79.320 ;
    END
  END addr_in_B[5]
  PIN addr_in_A[6]
    DIRECTION INPUT ;
    USE SIGNAL ;
    SHAPE ABUTMENT ;
    PORT
      LAYER M4 ;
      RECT 0.000 79.680 0.024 79.704 ;
    END
  END addr_in_A[6]
  PIN addr_in_B[6]
    DIRECTION INPUT ;
    USE SIGNAL ;
    SHAPE ABUTMENT ;
    PORT
      LAYER M4 ;
      RECT 93.836 79.680 93.860 79.704 ;
    END
  END addr_in_B[6]
  PIN addr_in_A[7]
    DIRECTION INPUT ;
    USE SIGNAL ;
    SHAPE ABUTMENT ;
    PORT
      LAYER M4 ;
      RECT 0.000 80.064 0.024 80.088 ;
    END
  END addr_in_A[7]
  PIN addr_in_B[7]
    DIRECTION INPUT ;
    USE SIGNAL ;
    SHAPE ABUTMENT ;
    PORT
      LAYER M4 ;
      RECT 93.836 80.064 93.860 80.088 ;
    END
  END addr_in_B[7]
  PIN addr_in_A[8]
    DIRECTION INPUT ;
    USE SIGNAL ;
    SHAPE ABUTMENT ;
    PORT
      LAYER M4 ;
      RECT 0.000 80.448 0.024 80.472 ;
    END
  END addr_in_A[8]
  PIN addr_in_B[8]
    DIRECTION INPUT ;
    USE SIGNAL ;
    SHAPE ABUTMENT ;
    PORT
      LAYER M4 ;
      RECT 93.836 80.448 93.860 80.472 ;
    END
  END addr_in_B[8]
  PIN addr_in_A[9]
    DIRECTION INPUT ;
    USE SIGNAL ;
    SHAPE ABUTMENT ;
    PORT
      LAYER M4 ;
      RECT 0.000 80.832 0.024 80.856 ;
    END
  END addr_in_A[9]
  PIN addr_in_B[9]
    DIRECTION INPUT ;
    USE SIGNAL ;
    SHAPE ABUTMENT ;
    PORT
      LAYER M4 ;
      RECT 93.836 80.832 93.860 80.856 ;
    END
  END addr_in_B[9]
  PIN addr_in_A[10]
    DIRECTION INPUT ;
    USE SIGNAL ;
    SHAPE ABUTMENT ;
    PORT
      LAYER M4 ;
      RECT 0.000 81.216 0.024 81.240 ;
    END
  END addr_in_A[10]
  PIN addr_in_B[10]
    DIRECTION INPUT ;
    USE SIGNAL ;
    SHAPE ABUTMENT ;
    PORT
      LAYER M4 ;
      RECT 93.836 81.216 93.860 81.240 ;
    END
  END addr_in_B[10]
  PIN we_in_A
    DIRECTION INPUT ;
    USE SIGNAL ;
    SHAPE ABUTMENT ;
    PORT
      LAYER M4 ;
      RECT 0.000 82.800 0.024 82.824 ;
    END
  END we_in_A
  PIN we_in_B
    DIRECTION INPUT ;
    USE SIGNAL ;
    SHAPE ABUTMENT ;
    PORT
      LAYER M4 ;
      RECT 93.836 82.800 93.860 82.824 ;
    END
  END we_in_B
  PIN ce_in
    DIRECTION INPUT ;
    USE SIGNAL ;
    SHAPE ABUTMENT ;
    PORT
      LAYER M4 ;
      RECT 0.000 83.184 0.024 83.208 ;
    END
  END ce_in
  PIN clk
    DIRECTION INPUT ;
    USE SIGNAL ;
    SHAPE ABUTMENT ;
    PORT
      LAYER M4 ;
      RECT 0.000 83.568 0.024 83.592 ;
    END
  END clk
  PIN VSS
    DIRECTION INOUT ;
    USE GROUND ;
    PORT
      LAYER M4 ;
      RECT 0.048 0.000 93.812 0.096 ;
      RECT 0.048 0.768 93.812 0.864 ;
      RECT 0.048 1.536 93.812 1.632 ;
      RECT 0.048 2.304 93.812 2.400 ;
      RECT 0.048 3.072 93.812 3.168 ;
      RECT 0.048 3.840 93.812 3.936 ;
      RECT 0.048 4.608 93.812 4.704 ;
      RECT 0.048 5.376 93.812 5.472 ;
      RECT 0.048 6.144 93.812 6.240 ;
      RECT 0.048 6.912 93.812 7.008 ;
      RECT 0.048 7.680 93.812 7.776 ;
      RECT 0.048 8.448 93.812 8.544 ;
      RECT 0.048 9.216 93.812 9.312 ;
      RECT 0.048 9.984 93.812 10.080 ;
      RECT 0.048 10.752 93.812 10.848 ;
      RECT 0.048 11.520 93.812 11.616 ;
      RECT 0.048 12.288 93.812 12.384 ;
      RECT 0.048 13.056 93.812 13.152 ;
      RECT 0.048 13.824 93.812 13.920 ;
      RECT 0.048 14.592 93.812 14.688 ;
      RECT 0.048 15.360 93.812 15.456 ;
      RECT 0.048 16.128 93.812 16.224 ;
      RECT 0.048 16.896 93.812 16.992 ;
      RECT 0.048 17.664 93.812 17.760 ;
      RECT 0.048 18.432 93.812 18.528 ;
      RECT 0.048 19.200 93.812 19.296 ;
      RECT 0.048 19.968 93.812 20.064 ;
      RECT 0.048 20.736 93.812 20.832 ;
      RECT 0.048 21.504 93.812 21.600 ;
      RECT 0.048 22.272 93.812 22.368 ;
      RECT 0.048 23.040 93.812 23.136 ;
      RECT 0.048 23.808 93.812 23.904 ;
      RECT 0.048 24.576 93.812 24.672 ;
      RECT 0.048 25.344 93.812 25.440 ;
      RECT 0.048 26.112 93.812 26.208 ;
      RECT 0.048 26.880 93.812 26.976 ;
      RECT 0.048 27.648 93.812 27.744 ;
      RECT 0.048 28.416 93.812 28.512 ;
      RECT 0.048 29.184 93.812 29.280 ;
      RECT 0.048 29.952 93.812 30.048 ;
      RECT 0.048 30.720 93.812 30.816 ;
      RECT 0.048 31.488 93.812 31.584 ;
      RECT 0.048 32.256 93.812 32.352 ;
      RECT 0.048 33.024 93.812 33.120 ;
      RECT 0.048 33.792 93.812 33.888 ;
      RECT 0.048 34.560 93.812 34.656 ;
      RECT 0.048 35.328 93.812 35.424 ;
      RECT 0.048 36.096 93.812 36.192 ;
      RECT 0.048 36.864 93.812 36.960 ;
      RECT 0.048 37.632 93.812 37.728 ;
      RECT 0.048 38.400 93.812 38.496 ;
      RECT 0.048 39.168 93.812 39.264 ;
      RECT 0.048 39.936 93.812 40.032 ;
      RECT 0.048 40.704 93.812 40.800 ;
      RECT 0.048 41.472 93.812 41.568 ;
      RECT 0.048 42.240 93.812 42.336 ;
      RECT 0.048 43.008 93.812 43.104 ;
      RECT 0.048 43.776 93.812 43.872 ;
      RECT 0.048 44.544 93.812 44.640 ;
      RECT 0.048 45.312 93.812 45.408 ;
      RECT 0.048 46.080 93.812 46.176 ;
      RECT 0.048 46.848 93.812 46.944 ;
      RECT 0.048 47.616 93.812 47.712 ;
      RECT 0.048 48.384 93.812 48.480 ;
      RECT 0.048 49.152 93.812 49.248 ;
      RECT 0.048 49.920 93.812 50.016 ;
      RECT 0.048 50.688 93.812 50.784 ;
      RECT 0.048 51.456 93.812 51.552 ;
      RECT 0.048 52.224 93.812 52.320 ;
      RECT 0.048 52.992 93.812 53.088 ;
      RECT 0.048 53.760 93.812 53.856 ;
      RECT 0.048 54.528 93.812 54.624 ;
      RECT 0.048 55.296 93.812 55.392 ;
      RECT 0.048 56.064 93.812 56.160 ;
      RECT 0.048 56.832 93.812 56.928 ;
      RECT 0.048 57.600 93.812 57.696 ;
      RECT 0.048 58.368 93.812 58.464 ;
      RECT 0.048 59.136 93.812 59.232 ;
      RECT 0.048 59.904 93.812 60.000 ;
      RECT 0.048 60.672 93.812 60.768 ;
      RECT 0.048 61.440 93.812 61.536 ;
      RECT 0.048 62.208 93.812 62.304 ;
      RECT 0.048 62.976 93.812 63.072 ;
      RECT 0.048 63.744 93.812 63.840 ;
      RECT 0.048 64.512 93.812 64.608 ;
      RECT 0.048 65.280 93.812 65.376 ;
      RECT 0.048 66.048 93.812 66.144 ;
      RECT 0.048 66.816 93.812 66.912 ;
      RECT 0.048 67.584 93.812 67.680 ;
      RECT 0.048 68.352 93.812 68.448 ;
      RECT 0.048 69.120 93.812 69.216 ;
      RECT 0.048 69.888 93.812 69.984 ;
      RECT 0.048 70.656 93.812 70.752 ;
      RECT 0.048 71.424 93.812 71.520 ;
      RECT 0.048 72.192 93.812 72.288 ;
      RECT 0.048 72.960 93.812 73.056 ;
      RECT 0.048 73.728 93.812 73.824 ;
      RECT 0.048 74.496 93.812 74.592 ;
      RECT 0.048 75.264 93.812 75.360 ;
      RECT 0.048 76.032 93.812 76.128 ;
      RECT 0.048 76.800 93.812 76.896 ;
      RECT 0.048 77.568 93.812 77.664 ;
      RECT 0.048 78.336 93.812 78.432 ;
      RECT 0.048 79.104 93.812 79.200 ;
      RECT 0.048 79.872 93.812 79.968 ;
      RECT 0.048 80.640 93.812 80.736 ;
      RECT 0.048 81.408 93.812 81.504 ;
      RECT 0.048 82.176 93.812 82.272 ;
      RECT 0.048 82.944 93.812 83.040 ;
      RECT 0.048 83.712 93.812 83.808 ;
    END
  END VSS
  PIN VDD
    DIRECTION INOUT ;
    USE POWER ;
    PORT
      LAYER M4 ;
      RECT 0.048 0.384 93.812 0.480 ;
      RECT 0.048 1.152 93.812 1.248 ;
      RECT 0.048 1.920 93.812 2.016 ;
      RECT 0.048 2.688 93.812 2.784 ;
      RECT 0.048 3.456 93.812 3.552 ;
      RECT 0.048 4.224 93.812 4.320 ;
      RECT 0.048 4.992 93.812 5.088 ;
      RECT 0.048 5.760 93.812 5.856 ;
      RECT 0.048 6.528 93.812 6.624 ;
      RECT 0.048 7.296 93.812 7.392 ;
      RECT 0.048 8.064 93.812 8.160 ;
      RECT 0.048 8.832 93.812 8.928 ;
      RECT 0.048 9.600 93.812 9.696 ;
      RECT 0.048 10.368 93.812 10.464 ;
      RECT 0.048 11.136 93.812 11.232 ;
      RECT 0.048 11.904 93.812 12.000 ;
      RECT 0.048 12.672 93.812 12.768 ;
      RECT 0.048 13.440 93.812 13.536 ;
      RECT 0.048 14.208 93.812 14.304 ;
      RECT 0.048 14.976 93.812 15.072 ;
      RECT 0.048 15.744 93.812 15.840 ;
      RECT 0.048 16.512 93.812 16.608 ;
      RECT 0.048 17.280 93.812 17.376 ;
      RECT 0.048 18.048 93.812 18.144 ;
      RECT 0.048 18.816 93.812 18.912 ;
      RECT 0.048 19.584 93.812 19.680 ;
      RECT 0.048 20.352 93.812 20.448 ;
      RECT 0.048 21.120 93.812 21.216 ;
      RECT 0.048 21.888 93.812 21.984 ;
      RECT 0.048 22.656 93.812 22.752 ;
      RECT 0.048 23.424 93.812 23.520 ;
      RECT 0.048 24.192 93.812 24.288 ;
      RECT 0.048 24.960 93.812 25.056 ;
      RECT 0.048 25.728 93.812 25.824 ;
      RECT 0.048 26.496 93.812 26.592 ;
      RECT 0.048 27.264 93.812 27.360 ;
      RECT 0.048 28.032 93.812 28.128 ;
      RECT 0.048 28.800 93.812 28.896 ;
      RECT 0.048 29.568 93.812 29.664 ;
      RECT 0.048 30.336 93.812 30.432 ;
      RECT 0.048 31.104 93.812 31.200 ;
      RECT 0.048 31.872 93.812 31.968 ;
      RECT 0.048 32.640 93.812 32.736 ;
      RECT 0.048 33.408 93.812 33.504 ;
      RECT 0.048 34.176 93.812 34.272 ;
      RECT 0.048 34.944 93.812 35.040 ;
      RECT 0.048 35.712 93.812 35.808 ;
      RECT 0.048 36.480 93.812 36.576 ;
      RECT 0.048 37.248 93.812 37.344 ;
      RECT 0.048 38.016 93.812 38.112 ;
      RECT 0.048 38.784 93.812 38.880 ;
      RECT 0.048 39.552 93.812 39.648 ;
      RECT 0.048 40.320 93.812 40.416 ;
      RECT 0.048 41.088 93.812 41.184 ;
      RECT 0.048 41.856 93.812 41.952 ;
      RECT 0.048 42.624 93.812 42.720 ;
      RECT 0.048 43.392 93.812 43.488 ;
      RECT 0.048 44.160 93.812 44.256 ;
      RECT 0.048 44.928 93.812 45.024 ;
      RECT 0.048 45.696 93.812 45.792 ;
      RECT 0.048 46.464 93.812 46.560 ;
      RECT 0.048 47.232 93.812 47.328 ;
      RECT 0.048 48.000 93.812 48.096 ;
      RECT 0.048 48.768 93.812 48.864 ;
      RECT 0.048 49.536 93.812 49.632 ;
      RECT 0.048 50.304 93.812 50.400 ;
      RECT 0.048 51.072 93.812 51.168 ;
      RECT 0.048 51.840 93.812 51.936 ;
      RECT 0.048 52.608 93.812 52.704 ;
      RECT 0.048 53.376 93.812 53.472 ;
      RECT 0.048 54.144 93.812 54.240 ;
      RECT 0.048 54.912 93.812 55.008 ;
      RECT 0.048 55.680 93.812 55.776 ;
      RECT 0.048 56.448 93.812 56.544 ;
      RECT 0.048 57.216 93.812 57.312 ;
      RECT 0.048 57.984 93.812 58.080 ;
      RECT 0.048 58.752 93.812 58.848 ;
      RECT 0.048 59.520 93.812 59.616 ;
      RECT 0.048 60.288 93.812 60.384 ;
      RECT 0.048 61.056 93.812 61.152 ;
      RECT 0.048 61.824 93.812 61.920 ;
      RECT 0.048 62.592 93.812 62.688 ;
      RECT 0.048 63.360 93.812 63.456 ;
      RECT 0.048 64.128 93.812 64.224 ;
      RECT 0.048 64.896 93.812 64.992 ;
      RECT 0.048 65.664 93.812 65.760 ;
      RECT 0.048 66.432 93.812 66.528 ;
      RECT 0.048 67.200 93.812 67.296 ;
      RECT 0.048 67.968 93.812 68.064 ;
      RECT 0.048 68.736 93.812 68.832 ;
      RECT 0.048 69.504 93.812 69.600 ;
      RECT 0.048 70.272 93.812 70.368 ;
      RECT 0.048 71.040 93.812 71.136 ;
      RECT 0.048 71.808 93.812 71.904 ;
      RECT 0.048 72.576 93.812 72.672 ;
      RECT 0.048 73.344 93.812 73.440 ;
      RECT 0.048 74.112 93.812 74.208 ;
      RECT 0.048 74.880 93.812 74.976 ;
      RECT 0.048 75.648 93.812 75.744 ;
      RECT 0.048 76.416 93.812 76.512 ;
      RECT 0.048 77.184 93.812 77.280 ;
      RECT 0.048 77.952 93.812 78.048 ;
      RECT 0.048 78.720 93.812 78.816 ;
      RECT 0.048 79.488 93.812 79.584 ;
      RECT 0.048 80.256 93.812 80.352 ;
      RECT 0.048 81.024 93.812 81.120 ;
      RECT 0.048 81.792 93.812 81.888 ;
      RECT 0.048 82.560 93.812 82.656 ;
      RECT 0.048 83.328 93.812 83.424 ;
    END
  END VDD
  OBS
    LAYER M1 ;
    RECT 0 0 93.860 84.000 ;
    LAYER M2 ;
    RECT 0 0 93.860 84.000 ;
    LAYER M3 ;
    RECT 0 0 93.860 84.000 ;
    LAYER M4 ;
    RECT 0 0 93.860 84.000 ;
  END
END fakeram7_dp_2048x64

END LIBRARY
